VERSION 5.7 ;
  NOWIREEXTENSIONATPIN ON ;
  DIVIDERCHAR "/" ;
  BUSBITCHARS "[]" ;
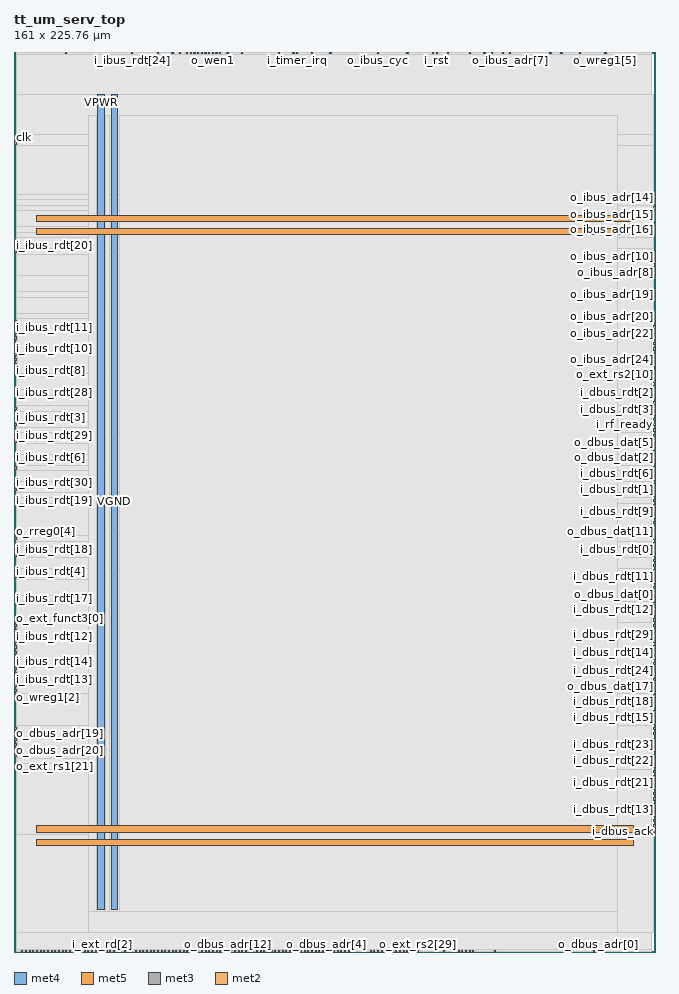
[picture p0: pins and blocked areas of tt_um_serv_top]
MACRO tt_um_serv_top
  CLASS BLOCK ;
  FOREIGN tt_um_serv_top ;
  ORIGIN 0.000 0.000 ;
  SIZE 161.000 BY 225.760 ;
  PIN VGND
    DIRECTION INOUT ;
    USE GROUND ;
    PORT
      LAYER met4 ;
        RECT 24.340 10.640 25.940 215.120 ;
    END
    PORT
      LAYER met5 ;
        RECT 5.520 30.030 155.480 31.630 ;
    END
    PORT
      LAYER met5 ;
        RECT 5.520 183.210 155.480 184.810 ;
    END
  END VGND
  PIN VPWR
    DIRECTION INOUT ;
    USE POWER ;
    PORT
      LAYER met4 ;
        RECT 21.040 10.640 22.640 215.120 ;
    END
    PORT
      LAYER met5 ;
        RECT 5.520 26.730 155.480 28.330 ;
    END
    PORT
      LAYER met5 ;
        RECT 5.520 179.910 155.480 181.510 ;
    END
  END VPWR
  PIN clk
    DIRECTION INPUT ;
    USE SIGNAL ;
    ANTENNAGATEAREA 0.852000 ;
    PORT
      LAYER met3 ;
        RECT 0.000 204.040 0.600 204.640 ;
    END
  END clk
  PIN i_dbus_ack
    DIRECTION INPUT ;
    USE SIGNAL ;
    ANTENNAGATEAREA 0.213000 ;
    PORT
      LAYER met3 ;
        RECT 160.400 29.960 161.000 30.560 ;
    END
  END i_dbus_ack
  PIN i_dbus_rdt[0]
    DIRECTION INPUT ;
    USE SIGNAL ;
    ANTENNAGATEAREA 0.213000 ;
    PORT
      LAYER met3 ;
        RECT 160.400 100.680 161.000 101.280 ;
    END
  END i_dbus_rdt[0]
  PIN i_dbus_rdt[10]
    DIRECTION INPUT ;
    USE SIGNAL ;
    ANTENNAGATEAREA 0.213000 ;
    PORT
      LAYER met3 ;
        RECT 160.400 141.480 161.000 142.080 ;
    END
  END i_dbus_rdt[10]
  PIN i_dbus_rdt[11]
    DIRECTION INPUT ;
    USE SIGNAL ;
    ANTENNAGATEAREA 0.213000 ;
    PORT
      LAYER met3 ;
        RECT 160.400 93.880 161.000 94.480 ;
    END
  END i_dbus_rdt[11]
  PIN i_dbus_rdt[12]
    DIRECTION INPUT ;
    USE SIGNAL ;
    ANTENNAGATEAREA 0.213000 ;
    PORT
      LAYER met3 ;
        RECT 160.400 85.720 161.000 86.320 ;
    END
  END i_dbus_rdt[12]
  PIN i_dbus_rdt[13]
    DIRECTION INPUT ;
    USE SIGNAL ;
    ANTENNAGATEAREA 0.213000 ;
    PORT
      LAYER met3 ;
        RECT 160.400 35.400 161.000 36.000 ;
    END
  END i_dbus_rdt[13]
  PIN i_dbus_rdt[14]
    DIRECTION INPUT ;
    USE SIGNAL ;
    ANTENNAGATEAREA 0.213000 ;
    PORT
      LAYER met3 ;
        RECT 160.400 74.840 161.000 75.440 ;
    END
  END i_dbus_rdt[14]
  PIN i_dbus_rdt[15]
    DIRECTION INPUT ;
    USE SIGNAL ;
    ANTENNAGATEAREA 0.213000 ;
    PORT
      LAYER met3 ;
        RECT 160.400 58.520 161.000 59.120 ;
    END
  END i_dbus_rdt[15]
  PIN i_dbus_rdt[16]
    DIRECTION INPUT ;
    USE SIGNAL ;
    ANTENNAGATEAREA 0.213000 ;
    PORT
      LAYER met3 ;
        RECT 160.400 76.200 161.000 76.800 ;
    END
  END i_dbus_rdt[16]
  PIN i_dbus_rdt[17]
    DIRECTION INPUT ;
    USE SIGNAL ;
    ANTENNAGATEAREA 0.213000 ;
    PORT
      LAYER met3 ;
        RECT 160.400 65.320 161.000 65.920 ;
    END
  END i_dbus_rdt[17]
  PIN i_dbus_rdt[18]
    DIRECTION INPUT ;
    USE SIGNAL ;
    ANTENNAGATEAREA 0.213000 ;
    PORT
      LAYER met3 ;
        RECT 160.400 62.600 161.000 63.200 ;
    END
  END i_dbus_rdt[18]
  PIN i_dbus_rdt[19]
    DIRECTION INPUT ;
    USE SIGNAL ;
    ANTENNAGATEAREA 0.213000 ;
    PORT
      LAYER met3 ;
        RECT 160.400 57.160 161.000 57.760 ;
    END
  END i_dbus_rdt[19]
  PIN i_dbus_rdt[1]
    DIRECTION INPUT ;
    USE SIGNAL ;
    ANTENNAGATEAREA 0.213000 ;
    PORT
      LAYER met3 ;
        RECT 160.400 115.640 161.000 116.240 ;
    END
  END i_dbus_rdt[1]
  PIN i_dbus_rdt[20]
    DIRECTION INPUT ;
    USE SIGNAL ;
    ANTENNAGATEAREA 0.213000 ;
    PORT
      LAYER met3 ;
        RECT 160.400 38.120 161.000 38.720 ;
    END
  END i_dbus_rdt[20]
  PIN i_dbus_rdt[21]
    DIRECTION INPUT ;
    USE SIGNAL ;
    ANTENNAGATEAREA 0.213000 ;
    PORT
      LAYER met3 ;
        RECT 160.400 42.200 161.000 42.800 ;
    END
  END i_dbus_rdt[21]
  PIN i_dbus_rdt[22]
    DIRECTION INPUT ;
    USE SIGNAL ;
    ANTENNAGATEAREA 0.213000 ;
    PORT
      LAYER met3 ;
        RECT 160.400 47.640 161.000 48.240 ;
    END
  END i_dbus_rdt[22]
  PIN i_dbus_rdt[23]
    DIRECTION INPUT ;
    USE SIGNAL ;
    ANTENNAGATEAREA 0.213000 ;
    PORT
      LAYER met3 ;
        RECT 160.400 51.720 161.000 52.320 ;
    END
  END i_dbus_rdt[23]
  PIN i_dbus_rdt[24]
    DIRECTION INPUT ;
    USE SIGNAL ;
    ANTENNAGATEAREA 0.213000 ;
    PORT
      LAYER met3 ;
        RECT 160.400 72.120 161.000 72.720 ;
    END
  END i_dbus_rdt[24]
  PIN i_dbus_rdt[25]
    DIRECTION INPUT ;
    USE SIGNAL ;
    ANTENNAGATEAREA 0.213000 ;
    PORT
      LAYER met2 ;
        RECT 114.170 0.000 114.450 0.280 ;
    END
  END i_dbus_rdt[25]
  PIN i_dbus_rdt[26]
    DIRECTION INPUT ;
    USE SIGNAL ;
    ANTENNAGATEAREA 0.213000 ;
    PORT
      LAYER met2 ;
        RECT 112.330 0.000 112.610 0.280 ;
    END
  END i_dbus_rdt[26]
  PIN i_dbus_rdt[27]
    DIRECTION INPUT ;
    USE SIGNAL ;
    ANTENNAGATEAREA 0.213000 ;
    PORT
      LAYER met2 ;
        RECT 107.730 0.000 108.010 0.280 ;
    END
  END i_dbus_rdt[27]
  PIN i_dbus_rdt[28]
    DIRECTION INPUT ;
    USE SIGNAL ;
    ANTENNAGATEAREA 0.213000 ;
    PORT
      LAYER met2 ;
        RECT 97.610 0.000 97.890 0.280 ;
    END
  END i_dbus_rdt[28]
  PIN i_dbus_rdt[29]
    DIRECTION INPUT ;
    USE SIGNAL ;
    ANTENNAGATEAREA 0.213000 ;
    PORT
      LAYER met3 ;
        RECT 160.400 77.560 161.000 78.160 ;
    END
  END i_dbus_rdt[29]
  PIN i_dbus_rdt[2]
    DIRECTION INPUT ;
    USE SIGNAL ;
    ANTENNAGATEAREA 0.213000 ;
    PORT
      LAYER met3 ;
        RECT 160.400 140.120 161.000 140.720 ;
    END
  END i_dbus_rdt[2]
  PIN i_dbus_rdt[30]
    DIRECTION INPUT ;
    USE SIGNAL ;
    ANTENNAGATEAREA 0.213000 ;
    PORT
      LAYER met2 ;
        RECT 92.090 0.000 92.370 0.280 ;
    END
  END i_dbus_rdt[30]
  PIN i_dbus_rdt[31]
    DIRECTION INPUT ;
    USE SIGNAL ;
    ANTENNAGATEAREA 0.213000 ;
    PORT
      LAYER met2 ;
        RECT 87.490 0.000 87.770 0.280 ;
    END
  END i_dbus_rdt[31]
  PIN i_dbus_rdt[3]
    DIRECTION INPUT ;
    USE SIGNAL ;
    ANTENNAGATEAREA 0.213000 ;
    PORT
      LAYER met3 ;
        RECT 160.400 137.400 161.000 138.000 ;
    END
  END i_dbus_rdt[3]
  PIN i_dbus_rdt[4]
    DIRECTION INPUT ;
    USE SIGNAL ;
    ANTENNAGATEAREA 0.213000 ;
    PORT
      LAYER met3 ;
        RECT 160.400 122.440 161.000 123.040 ;
    END
  END i_dbus_rdt[4]
  PIN i_dbus_rdt[5]
    DIRECTION INPUT ;
    USE SIGNAL ;
    ANTENNAGATEAREA 0.213000 ;
    PORT
      LAYER met3 ;
        RECT 160.400 121.080 161.000 121.680 ;
    END
  END i_dbus_rdt[5]
  PIN i_dbus_rdt[6]
    DIRECTION INPUT ;
    USE SIGNAL ;
    ANTENNAGATEAREA 0.213000 ;
    PORT
      LAYER met3 ;
        RECT 160.400 119.720 161.000 120.320 ;
    END
  END i_dbus_rdt[6]
  PIN i_dbus_rdt[7]
    DIRECTION INPUT ;
    USE SIGNAL ;
    ANTENNAGATEAREA 0.213000 ;
    PORT
      LAYER met3 ;
        RECT 160.400 102.040 161.000 102.640 ;
    END
  END i_dbus_rdt[7]
  PIN i_dbus_rdt[8]
    DIRECTION INPUT ;
    USE SIGNAL ;
    ANTENNAGATEAREA 0.213000 ;
    PORT
      LAYER met3 ;
        RECT 160.400 99.320 161.000 99.920 ;
    END
  END i_dbus_rdt[8]
  PIN i_dbus_rdt[9]
    DIRECTION INPUT ;
    USE SIGNAL ;
    ANTENNAGATEAREA 0.213000 ;
    PORT
      LAYER met3 ;
        RECT 160.400 110.200 161.000 110.800 ;
    END
  END i_dbus_rdt[9]
  PIN i_ext_rd[0]
    DIRECTION INPUT ;
    USE SIGNAL ;
    PORT
      LAYER met2 ;
        RECT 9.290 0.000 9.570 0.280 ;
    END
  END i_ext_rd[0]
  PIN i_ext_rd[10]
    DIRECTION INPUT ;
    USE SIGNAL ;
    PORT
      LAYER met2 ;
        RECT 4.690 0.000 4.970 0.280 ;
    END
  END i_ext_rd[10]
  PIN i_ext_rd[11]
    DIRECTION INPUT ;
    USE SIGNAL ;
    PORT
      LAYER met2 ;
        RECT 58.970 0.000 59.250 0.280 ;
    END
  END i_ext_rd[11]
  PIN i_ext_rd[12]
    DIRECTION INPUT ;
    USE SIGNAL ;
    PORT
      LAYER met2 ;
        RECT 14.810 0.000 15.090 0.280 ;
    END
  END i_ext_rd[12]
  PIN i_ext_rd[13]
    DIRECTION INPUT ;
    USE SIGNAL ;
    PORT
      LAYER met2 ;
        RECT 5.610 0.000 5.890 0.280 ;
    END
  END i_ext_rd[13]
  PIN i_ext_rd[14]
    DIRECTION INPUT ;
    USE SIGNAL ;
    PORT
      LAYER met2 ;
        RECT 12.970 0.000 13.250 0.280 ;
    END
  END i_ext_rd[14]
  PIN i_ext_rd[15]
    DIRECTION INPUT ;
    USE SIGNAL ;
    PORT
      LAYER met2 ;
        RECT 13.890 0.000 14.170 0.280 ;
    END
  END i_ext_rd[15]
  PIN i_ext_rd[16]
    DIRECTION INPUT ;
    USE SIGNAL ;
    PORT
      LAYER met2 ;
        RECT 2.850 0.000 3.130 0.280 ;
    END
  END i_ext_rd[16]
  PIN i_ext_rd[17]
    DIRECTION INPUT ;
    USE SIGNAL ;
    PORT
      LAYER met2 ;
        RECT 21.250 0.000 21.530 0.280 ;
    END
  END i_ext_rd[17]
  PIN i_ext_rd[18]
    DIRECTION INPUT ;
    USE SIGNAL ;
    PORT
      LAYER met2 ;
        RECT 16.650 0.000 16.930 0.280 ;
    END
  END i_ext_rd[18]
  PIN i_ext_rd[19]
    DIRECTION INPUT ;
    USE SIGNAL ;
    PORT
      LAYER met2 ;
        RECT 11.130 0.000 11.410 0.280 ;
    END
  END i_ext_rd[19]
  PIN i_ext_rd[1]
    DIRECTION INPUT ;
    USE SIGNAL ;
    PORT
      LAYER met2 ;
        RECT 15.730 0.000 16.010 0.280 ;
    END
  END i_ext_rd[1]
  PIN i_ext_rd[20]
    DIRECTION INPUT ;
    USE SIGNAL ;
    PORT
      LAYER met2 ;
        RECT 17.570 0.000 17.850 0.280 ;
    END
  END i_ext_rd[20]
  PIN i_ext_rd[21]
    DIRECTION INPUT ;
    USE SIGNAL ;
    PORT
      LAYER met2 ;
        RECT 69.090 0.000 69.370 0.280 ;
    END
  END i_ext_rd[21]
  PIN i_ext_rd[22]
    DIRECTION INPUT ;
    USE SIGNAL ;
    PORT
      LAYER met2 ;
        RECT 67.250 0.000 67.530 0.280 ;
    END
  END i_ext_rd[22]
  PIN i_ext_rd[23]
    DIRECTION INPUT ;
    USE SIGNAL ;
    PORT
      LAYER met2 ;
        RECT 20.330 0.000 20.610 0.280 ;
    END
  END i_ext_rd[23]
  PIN i_ext_rd[24]
    DIRECTION INPUT ;
    USE SIGNAL ;
    PORT
      LAYER met2 ;
        RECT 75.530 0.000 75.810 0.280 ;
    END
  END i_ext_rd[24]
  PIN i_ext_rd[25]
    DIRECTION INPUT ;
    USE SIGNAL ;
    PORT
      LAYER met2 ;
        RECT 83.810 0.000 84.090 0.280 ;
    END
  END i_ext_rd[25]
  PIN i_ext_rd[26]
    DIRECTION INPUT ;
    USE SIGNAL ;
    PORT
      LAYER met2 ;
        RECT 18.490 0.000 18.770 0.280 ;
    END
  END i_ext_rd[26]
  PIN i_ext_rd[27]
    DIRECTION INPUT ;
    USE SIGNAL ;
    PORT
      LAYER met2 ;
        RECT 19.410 0.000 19.690 0.280 ;
    END
  END i_ext_rd[27]
  PIN i_ext_rd[28]
    DIRECTION INPUT ;
    USE SIGNAL ;
    PORT
      LAYER met2 ;
        RECT 36.890 0.000 37.170 0.280 ;
    END
  END i_ext_rd[28]
  PIN i_ext_rd[29]
    DIRECTION INPUT ;
    USE SIGNAL ;
    PORT
      LAYER met2 ;
        RECT 1.930 0.000 2.210 0.280 ;
    END
  END i_ext_rd[29]
  PIN i_ext_rd[2]
    DIRECTION INPUT ;
    USE SIGNAL ;
    PORT
      LAYER met2 ;
        RECT 22.170 0.000 22.450 0.280 ;
    END
  END i_ext_rd[2]
  PIN i_ext_rd[30]
    DIRECTION INPUT ;
    USE SIGNAL ;
    PORT
      LAYER met2 ;
        RECT 3.770 0.000 4.050 0.280 ;
    END
  END i_ext_rd[30]
  PIN i_ext_rd[31]
    DIRECTION INPUT ;
    USE SIGNAL ;
    PORT
      LAYER met2 ;
        RECT 8.370 0.000 8.650 0.280 ;
    END
  END i_ext_rd[31]
  PIN i_ext_rd[3]
    DIRECTION INPUT ;
    USE SIGNAL ;
    PORT
      LAYER met2 ;
        RECT 6.530 0.000 6.810 0.280 ;
    END
  END i_ext_rd[3]
  PIN i_ext_rd[4]
    DIRECTION INPUT ;
    USE SIGNAL ;
    PORT
      LAYER met2 ;
        RECT 54.370 0.000 54.650 0.280 ;
    END
  END i_ext_rd[4]
  PIN i_ext_rd[5]
    DIRECTION INPUT ;
    USE SIGNAL ;
    PORT
      LAYER met2 ;
        RECT 7.450 0.000 7.730 0.280 ;
    END
  END i_ext_rd[5]
  PIN i_ext_rd[6]
    DIRECTION INPUT ;
    USE SIGNAL ;
    PORT
      LAYER met2 ;
        RECT 38.730 0.000 39.010 0.280 ;
    END
  END i_ext_rd[6]
  PIN i_ext_rd[7]
    DIRECTION INPUT ;
    USE SIGNAL ;
    PORT
      LAYER met2 ;
        RECT 10.210 0.000 10.490 0.280 ;
    END
  END i_ext_rd[7]
  PIN i_ext_rd[8]
    DIRECTION INPUT ;
    USE SIGNAL ;
    PORT
      LAYER met2 ;
        RECT 55.290 0.000 55.570 0.280 ;
    END
  END i_ext_rd[8]
  PIN i_ext_rd[9]
    DIRECTION INPUT ;
    USE SIGNAL ;
    PORT
      LAYER met2 ;
        RECT 30.450 0.000 30.730 0.280 ;
    END
  END i_ext_rd[9]
  PIN i_ext_ready
    DIRECTION INPUT ;
    USE SIGNAL ;
    PORT
      LAYER met2 ;
        RECT 31.370 0.000 31.650 0.280 ;
    END
  END i_ext_ready
  PIN i_ibus_ack
    DIRECTION INPUT ;
    USE SIGNAL ;
    ANTENNAGATEAREA 0.213000 ;
    PORT
      LAYER met3 ;
        RECT 0.000 202.680 0.600 203.280 ;
    END
  END i_ibus_ack
  PIN i_ibus_rdt[0]
    DIRECTION INPUT ;
    USE SIGNAL ;
    PORT
      LAYER met2 ;
        RECT 65.410 0.000 65.690 0.280 ;
    END
  END i_ibus_rdt[0]
  PIN i_ibus_rdt[10]
    DIRECTION INPUT ;
    USE SIGNAL ;
    ANTENNAGATEAREA 0.213000 ;
    PORT
      LAYER met3 ;
        RECT 0.000 151.000 0.600 151.600 ;
    END
  END i_ibus_rdt[10]
  PIN i_ibus_rdt[11]
    DIRECTION INPUT ;
    USE SIGNAL ;
    ANTENNAGATEAREA 0.213000 ;
    PORT
      LAYER met3 ;
        RECT 0.000 156.440 0.600 157.040 ;
    END
  END i_ibus_rdt[11]
  PIN i_ibus_rdt[12]
    DIRECTION INPUT ;
    USE SIGNAL ;
    ANTENNAGATEAREA 0.213000 ;
    PORT
      LAYER met3 ;
        RECT 0.000 78.920 0.600 79.520 ;
    END
  END i_ibus_rdt[12]
  PIN i_ibus_rdt[13]
    DIRECTION INPUT ;
    USE SIGNAL ;
    ANTENNAGATEAREA 0.213000 ;
    PORT
      LAYER met3 ;
        RECT 0.000 68.040 0.600 68.640 ;
    END
  END i_ibus_rdt[13]
  PIN i_ibus_rdt[14]
    DIRECTION INPUT ;
    USE SIGNAL ;
    ANTENNAGATEAREA 0.213000 ;
    PORT
      LAYER met3 ;
        RECT 0.000 70.760 0.600 71.360 ;
    END
  END i_ibus_rdt[14]
  PIN i_ibus_rdt[15]
    DIRECTION INPUT ;
    USE SIGNAL ;
    ANTENNAGATEAREA 0.213000 ;
    PORT
      LAYER met3 ;
        RECT 0.000 72.120 0.600 72.720 ;
    END
  END i_ibus_rdt[15]
  PIN i_ibus_rdt[16]
    DIRECTION INPUT ;
    USE SIGNAL ;
    ANTENNAGATEAREA 0.213000 ;
    PORT
      LAYER met3 ;
        RECT 0.000 77.560 0.600 78.160 ;
    END
  END i_ibus_rdt[16]
  PIN i_ibus_rdt[17]
    DIRECTION INPUT ;
    USE SIGNAL ;
    ANTENNAGATEAREA 0.213000 ;
    PORT
      LAYER met3 ;
        RECT 0.000 88.440 0.600 89.040 ;
    END
  END i_ibus_rdt[17]
  PIN i_ibus_rdt[18]
    DIRECTION INPUT ;
    USE SIGNAL ;
    ANTENNAGATEAREA 0.213000 ;
    PORT
      LAYER met3 ;
        RECT 0.000 100.680 0.600 101.280 ;
    END
  END i_ibus_rdt[18]
  PIN i_ibus_rdt[19]
    DIRECTION INPUT ;
    USE SIGNAL ;
    ANTENNAGATEAREA 0.213000 ;
    PORT
      LAYER met3 ;
        RECT 0.000 112.920 0.600 113.520 ;
    END
  END i_ibus_rdt[19]
  PIN i_ibus_rdt[1]
    DIRECTION INPUT ;
    USE SIGNAL ;
    PORT
      LAYER met2 ;
        RECT 70.010 0.000 70.290 0.280 ;
    END
  END i_ibus_rdt[1]
  PIN i_ibus_rdt[20]
    DIRECTION INPUT ;
    USE SIGNAL ;
    ANTENNAGATEAREA 0.213000 ;
    PORT
      LAYER met3 ;
        RECT 0.000 176.840 0.600 177.440 ;
    END
  END i_ibus_rdt[20]
  PIN i_ibus_rdt[21]
    DIRECTION INPUT ;
    USE SIGNAL ;
    ANTENNAGATEAREA 0.213000 ;
    PORT
      LAYER met2 ;
        RECT 50.690 225.480 50.970 225.760 ;
    END
  END i_ibus_rdt[21]
  PIN i_ibus_rdt[22]
    DIRECTION INPUT ;
    USE SIGNAL ;
    ANTENNAGATEAREA 0.213000 ;
    PORT
      LAYER met2 ;
        RECT 53.450 225.480 53.730 225.760 ;
    END
  END i_ibus_rdt[22]
  PIN i_ibus_rdt[23]
    DIRECTION INPUT ;
    USE SIGNAL ;
    ANTENNAGATEAREA 0.213000 ;
    PORT
      LAYER met2 ;
        RECT 35.970 225.480 36.250 225.760 ;
    END
  END i_ibus_rdt[23]
  PIN i_ibus_rdt[24]
    DIRECTION INPUT ;
    USE SIGNAL ;
    ANTENNAGATEAREA 0.213000 ;
    PORT
      LAYER met2 ;
        RECT 29.530 225.480 29.810 225.760 ;
    END
  END i_ibus_rdt[24]
  PIN i_ibus_rdt[25]
    DIRECTION INPUT ;
    USE SIGNAL ;
    ANTENNAGATEAREA 0.213000 ;
    PORT
      LAYER met3 ;
        RECT 0.000 178.200 0.600 178.800 ;
    END
  END i_ibus_rdt[25]
  PIN i_ibus_rdt[26]
    DIRECTION INPUT ;
    USE SIGNAL ;
    ANTENNAGATEAREA 0.213000 ;
    PORT
      LAYER met3 ;
        RECT 0.000 175.480 0.600 176.080 ;
    END
  END i_ibus_rdt[26]
  PIN i_ibus_rdt[27]
    DIRECTION INPUT ;
    USE SIGNAL ;
    ANTENNAGATEAREA 0.213000 ;
    PORT
      LAYER met3 ;
        RECT 0.000 157.800 0.600 158.400 ;
    END
  END i_ibus_rdt[27]
  PIN i_ibus_rdt[28]
    DIRECTION INPUT ;
    USE SIGNAL ;
    ANTENNAGATEAREA 0.213000 ;
    PORT
      LAYER met3 ;
        RECT 0.000 140.120 0.600 140.720 ;
    END
  END i_ibus_rdt[28]
  PIN i_ibus_rdt[29]
    DIRECTION INPUT ;
    USE SIGNAL ;
    ANTENNAGATEAREA 0.213000 ;
    PORT
      LAYER met3 ;
        RECT 0.000 129.240 0.600 129.840 ;
    END
  END i_ibus_rdt[29]
  PIN i_ibus_rdt[2]
    DIRECTION INPUT ;
    USE SIGNAL ;
    ANTENNAGATEAREA 0.213000 ;
    PORT
      LAYER met2 ;
        RECT 47.930 225.480 48.210 225.760 ;
    END
  END i_ibus_rdt[2]
  PIN i_ibus_rdt[30]
    DIRECTION INPUT ;
    USE SIGNAL ;
    ANTENNAGATEAREA 0.213000 ;
    PORT
      LAYER met3 ;
        RECT 0.000 115.640 0.600 116.240 ;
    END
  END i_ibus_rdt[30]
  PIN i_ibus_rdt[31]
    DIRECTION INPUT ;
    USE SIGNAL ;
    ANTENNAGATEAREA 0.213000 ;
    PORT
      LAYER met3 ;
        RECT 0.000 117.000 0.600 117.600 ;
    END
  END i_ibus_rdt[31]
  PIN i_ibus_rdt[3]
    DIRECTION INPUT ;
    USE SIGNAL ;
    ANTENNAGATEAREA 0.213000 ;
    PORT
      LAYER met3 ;
        RECT 0.000 131.960 0.600 132.560 ;
    END
  END i_ibus_rdt[3]
  PIN i_ibus_rdt[4]
    DIRECTION INPUT ;
    USE SIGNAL ;
    ANTENNAGATEAREA 0.213000 ;
    PORT
      LAYER met3 ;
        RECT 0.000 95.240 0.600 95.840 ;
    END
  END i_ibus_rdt[4]
  PIN i_ibus_rdt[5]
    DIRECTION INPUT ;
    USE SIGNAL ;
    ANTENNAGATEAREA 0.213000 ;
    PORT
      LAYER met2 ;
        RECT 57.130 225.480 57.410 225.760 ;
    END
  END i_ibus_rdt[5]
  PIN i_ibus_rdt[6]
    DIRECTION INPUT ;
    USE SIGNAL ;
    ANTENNAGATEAREA 0.213000 ;
    PORT
      LAYER met3 ;
        RECT 0.000 123.800 0.600 124.400 ;
    END
  END i_ibus_rdt[6]
  PIN i_ibus_rdt[7]
    DIRECTION INPUT ;
    USE SIGNAL ;
    ANTENNAGATEAREA 0.213000 ;
    PORT
      LAYER met3 ;
        RECT 0.000 127.880 0.600 128.480 ;
    END
  END i_ibus_rdt[7]
  PIN i_ibus_rdt[8]
    DIRECTION INPUT ;
    USE SIGNAL ;
    ANTENNAGATEAREA 0.213000 ;
    PORT
      LAYER met3 ;
        RECT 0.000 145.560 0.600 146.160 ;
    END
  END i_ibus_rdt[8]
  PIN i_ibus_rdt[9]
    DIRECTION INPUT ;
    USE SIGNAL ;
    ANTENNAGATEAREA 0.213000 ;
    PORT
      LAYER met3 ;
        RECT 0.000 146.920 0.600 147.520 ;
    END
  END i_ibus_rdt[9]
  PIN i_rdata0
    DIRECTION INPUT ;
    USE SIGNAL ;
    ANTENNAGATEAREA 0.213000 ;
    PORT
      LAYER met3 ;
        RECT 0.000 99.320 0.600 99.920 ;
    END
  END i_rdata0
  PIN i_rdata1
    DIRECTION INPUT ;
    USE SIGNAL ;
    ANTENNAGATEAREA 0.213000 ;
    PORT
      LAYER met2 ;
        RECT 79.210 225.480 79.490 225.760 ;
    END
  END i_rdata1
  PIN i_rf_ready
    DIRECTION INPUT ;
    USE SIGNAL ;
    ANTENNAGATEAREA 0.213000 ;
    PORT
      LAYER met3 ;
        RECT 160.400 131.960 161.000 132.560 ;
    END
  END i_rf_ready
  PIN i_rst
    DIRECTION INPUT ;
    USE SIGNAL ;
    ANTENNAGATEAREA 0.213000 ;
    PORT
      LAYER met2 ;
        RECT 105.890 225.480 106.170 225.760 ;
    END
  END i_rst
  PIN i_timer_irq
    DIRECTION INPUT ;
    USE SIGNAL ;
    ANTENNAGATEAREA 0.213000 ;
    PORT
      LAYER met2 ;
        RECT 70.930 225.480 71.210 225.760 ;
    END
  END i_timer_irq
  PIN o_dbus_adr[0]
    DIRECTION OUTPUT ;
    USE SIGNAL ;
    PORT
      LAYER met2 ;
        RECT 146.370 0.000 146.650 0.280 ;
    END
  END o_dbus_adr[0]
  PIN o_dbus_adr[10]
    DIRECTION OUTPUT ;
    USE SIGNAL ;
    ANTENNADIFFAREA 0.702900 ;
    PORT
      LAYER met2 ;
        RECT 62.650 0.000 62.930 0.280 ;
    END
  END o_dbus_adr[10]
  PIN o_dbus_adr[11]
    DIRECTION OUTPUT ;
    USE SIGNAL ;
    ANTENNADIFFAREA 0.702900 ;
    PORT
      LAYER met2 ;
        RECT 58.050 0.000 58.330 0.280 ;
    END
  END o_dbus_adr[11]
  PIN o_dbus_adr[12]
    DIRECTION OUTPUT ;
    USE SIGNAL ;
    ANTENNADIFFAREA 0.702900 ;
    PORT
      LAYER met2 ;
        RECT 53.450 0.000 53.730 0.280 ;
    END
  END o_dbus_adr[12]
  PIN o_dbus_adr[13]
    DIRECTION OUTPUT ;
    USE SIGNAL ;
    ANTENNADIFFAREA 0.702900 ;
    PORT
      LAYER met2 ;
        RECT 52.530 0.000 52.810 0.280 ;
    END
  END o_dbus_adr[13]
  PIN o_dbus_adr[14]
    DIRECTION OUTPUT ;
    USE SIGNAL ;
    ANTENNADIFFAREA 0.702900 ;
    PORT
      LAYER met2 ;
        RECT 46.090 0.000 46.370 0.280 ;
    END
  END o_dbus_adr[14]
  PIN o_dbus_adr[15]
    DIRECTION OUTPUT ;
    USE SIGNAL ;
    ANTENNADIFFAREA 0.702900 ;
    PORT
      LAYER met2 ;
        RECT 45.170 0.000 45.450 0.280 ;
    END
  END o_dbus_adr[15]
  PIN o_dbus_adr[16]
    DIRECTION OUTPUT ;
    USE SIGNAL ;
    ANTENNADIFFAREA 0.702900 ;
    PORT
      LAYER met2 ;
        RECT 42.410 0.000 42.690 0.280 ;
    END
  END o_dbus_adr[16]
  PIN o_dbus_adr[17]
    DIRECTION OUTPUT ;
    USE SIGNAL ;
    ANTENNADIFFAREA 0.702900 ;
    PORT
      LAYER met2 ;
        RECT 37.810 0.000 38.090 0.280 ;
    END
  END o_dbus_adr[17]
  PIN o_dbus_adr[18]
    DIRECTION OUTPUT ;
    USE SIGNAL ;
    ANTENNADIFFAREA 0.702900 ;
    PORT
      LAYER met2 ;
        RECT 33.210 0.000 33.490 0.280 ;
    END
  END o_dbus_adr[18]
  PIN o_dbus_adr[19]
    DIRECTION OUTPUT ;
    USE SIGNAL ;
    ANTENNADIFFAREA 0.702900 ;
    PORT
      LAYER met3 ;
        RECT 0.000 54.440 0.600 55.040 ;
    END
  END o_dbus_adr[19]
  PIN o_dbus_adr[1]
    DIRECTION OUTPUT ;
    USE SIGNAL ;
    PORT
      LAYER met2 ;
        RECT 12.970 225.480 13.250 225.760 ;
    END
  END o_dbus_adr[1]
  PIN o_dbus_adr[20]
    DIRECTION OUTPUT ;
    USE SIGNAL ;
    ANTENNADIFFAREA 0.702900 ;
    PORT
      LAYER met3 ;
        RECT 0.000 50.360 0.600 50.960 ;
    END
  END o_dbus_adr[20]
  PIN o_dbus_adr[21]
    DIRECTION OUTPUT ;
    USE SIGNAL ;
    ANTENNADIFFAREA 0.702900 ;
    PORT
      LAYER met3 ;
        RECT 0.000 49.000 0.600 49.600 ;
    END
  END o_dbus_adr[21]
  PIN o_dbus_adr[22]
    DIRECTION OUTPUT ;
    USE SIGNAL ;
    ANTENNADIFFAREA 0.702900 ;
    PORT
      LAYER met2 ;
        RECT 23.090 0.000 23.370 0.280 ;
    END
  END o_dbus_adr[22]
  PIN o_dbus_adr[23]
    DIRECTION OUTPUT ;
    USE SIGNAL ;
    ANTENNADIFFAREA 0.702900 ;
    PORT
      LAYER met2 ;
        RECT 24.010 0.000 24.290 0.280 ;
    END
  END o_dbus_adr[23]
  PIN o_dbus_adr[24]
    DIRECTION OUTPUT ;
    USE SIGNAL ;
    ANTENNADIFFAREA 0.702900 ;
    PORT
      LAYER met2 ;
        RECT 27.690 0.000 27.970 0.280 ;
    END
  END o_dbus_adr[24]
  PIN o_dbus_adr[25]
    DIRECTION OUTPUT ;
    USE SIGNAL ;
    ANTENNADIFFAREA 0.702900 ;
    PORT
      LAYER met2 ;
        RECT 28.610 0.000 28.890 0.280 ;
    END
  END o_dbus_adr[25]
  PIN o_dbus_adr[26]
    DIRECTION OUTPUT ;
    USE SIGNAL ;
    ANTENNADIFFAREA 0.702900 ;
    PORT
      LAYER met2 ;
        RECT 32.290 0.000 32.570 0.280 ;
    END
  END o_dbus_adr[26]
  PIN o_dbus_adr[27]
    DIRECTION OUTPUT ;
    USE SIGNAL ;
    ANTENNADIFFAREA 0.702900 ;
    PORT
      LAYER met2 ;
        RECT 35.050 0.000 35.330 0.280 ;
    END
  END o_dbus_adr[27]
  PIN o_dbus_adr[28]
    DIRECTION OUTPUT ;
    USE SIGNAL ;
    ANTENNADIFFAREA 0.702900 ;
    PORT
      LAYER met2 ;
        RECT 40.570 0.000 40.850 0.280 ;
    END
  END o_dbus_adr[28]
  PIN o_dbus_adr[29]
    DIRECTION OUTPUT ;
    USE SIGNAL ;
    ANTENNADIFFAREA 0.702900 ;
    PORT
      LAYER met2 ;
        RECT 49.770 0.000 50.050 0.280 ;
    END
  END o_dbus_adr[29]
  PIN o_dbus_adr[2]
    DIRECTION OUTPUT ;
    USE SIGNAL ;
    ANTENNADIFFAREA 0.702900 ;
    PORT
      LAYER met2 ;
        RECT 71.850 0.000 72.130 0.280 ;
    END
  END o_dbus_adr[2]
  PIN o_dbus_adr[30]
    DIRECTION OUTPUT ;
    USE SIGNAL ;
    ANTENNADIFFAREA 0.702900 ;
    PORT
      LAYER met2 ;
        RECT 50.690 0.000 50.970 0.280 ;
    END
  END o_dbus_adr[30]
  PIN o_dbus_adr[31]
    DIRECTION OUTPUT ;
    USE SIGNAL ;
    ANTENNADIFFAREA 0.702900 ;
    PORT
      LAYER met2 ;
        RECT 61.730 0.000 62.010 0.280 ;
    END
  END o_dbus_adr[31]
  PIN o_dbus_adr[3]
    DIRECTION OUTPUT ;
    USE SIGNAL ;
    ANTENNADIFFAREA 0.702900 ;
    PORT
      LAYER met2 ;
        RECT 74.610 0.000 74.890 0.280 ;
    END
  END o_dbus_adr[3]
  PIN o_dbus_adr[4]
    DIRECTION OUTPUT ;
    USE SIGNAL ;
    ANTENNADIFFAREA 0.702900 ;
    PORT
      LAYER met2 ;
        RECT 78.290 0.000 78.570 0.280 ;
    END
  END o_dbus_adr[4]
  PIN o_dbus_adr[5]
    DIRECTION OUTPUT ;
    USE SIGNAL ;
    ANTENNADIFFAREA 0.702900 ;
    PORT
      LAYER met2 ;
        RECT 82.890 0.000 83.170 0.280 ;
    END
  END o_dbus_adr[5]
  PIN o_dbus_adr[6]
    DIRECTION OUTPUT ;
    USE SIGNAL ;
    ANTENNADIFFAREA 0.702900 ;
    PORT
      LAYER met2 ;
        RECT 79.210 0.000 79.490 0.280 ;
    END
  END o_dbus_adr[6]
  PIN o_dbus_adr[7]
    DIRECTION OUTPUT ;
    USE SIGNAL ;
    ANTENNADIFFAREA 0.702900 ;
    PORT
      LAYER met2 ;
        RECT 72.770 0.000 73.050 0.280 ;
    END
  END o_dbus_adr[7]
  PIN o_dbus_adr[8]
    DIRECTION OUTPUT ;
    USE SIGNAL ;
    ANTENNADIFFAREA 0.702900 ;
    PORT
      LAYER met2 ;
        RECT 68.170 0.000 68.450 0.280 ;
    END
  END o_dbus_adr[8]
  PIN o_dbus_adr[9]
    DIRECTION OUTPUT ;
    USE SIGNAL ;
    ANTENNADIFFAREA 0.702900 ;
    PORT
      LAYER met2 ;
        RECT 64.490 0.000 64.770 0.280 ;
    END
  END o_dbus_adr[9]
  PIN o_dbus_cyc
    DIRECTION OUTPUT ;
    USE SIGNAL ;
    ANTENNADIFFAREA 0.702900 ;
    PORT
      LAYER met3 ;
        RECT 160.400 117.000 161.000 117.600 ;
    END
  END o_dbus_cyc
  PIN o_dbus_dat[0]
    DIRECTION OUTPUT ;
    USE SIGNAL ;
    ANTENNADIFFAREA 0.702900 ;
    PORT
      LAYER met3 ;
        RECT 160.400 91.160 161.000 91.760 ;
    END
  END o_dbus_dat[0]
  PIN o_dbus_dat[10]
    DIRECTION OUTPUT ;
    USE SIGNAL ;
    ANTENNADIFFAREA 0.702900 ;
    PORT
      LAYER met3 ;
        RECT 160.400 114.280 161.000 114.880 ;
    END
  END o_dbus_dat[10]
  PIN o_dbus_dat[11]
    DIRECTION OUTPUT ;
    USE SIGNAL ;
    ANTENNADIFFAREA 0.702900 ;
    PORT
      LAYER met3 ;
        RECT 160.400 103.400 161.000 104.000 ;
    END
  END o_dbus_dat[11]
  PIN o_dbus_dat[12]
    DIRECTION OUTPUT ;
    USE SIGNAL ;
    ANTENNADIFFAREA 0.702900 ;
    PORT
      LAYER met3 ;
        RECT 160.400 87.080 161.000 87.680 ;
    END
  END o_dbus_dat[12]
  PIN o_dbus_dat[13]
    DIRECTION OUTPUT ;
    USE SIGNAL ;
    ANTENNADIFFAREA 0.702900 ;
    PORT
      LAYER met3 ;
        RECT 160.400 80.280 161.000 80.880 ;
    END
  END o_dbus_dat[13]
  PIN o_dbus_dat[14]
    DIRECTION OUTPUT ;
    USE SIGNAL ;
    ANTENNADIFFAREA 0.702900 ;
    PORT
      LAYER met3 ;
        RECT 160.400 73.480 161.000 74.080 ;
    END
  END o_dbus_dat[14]
  PIN o_dbus_dat[15]
    DIRECTION OUTPUT ;
    USE SIGNAL ;
    ANTENNADIFFAREA 0.702900 ;
    PORT
      LAYER met3 ;
        RECT 160.400 59.880 161.000 60.480 ;
    END
  END o_dbus_dat[15]
  PIN o_dbus_dat[16]
    DIRECTION OUTPUT ;
    USE SIGNAL ;
    ANTENNADIFFAREA 0.702900 ;
    PORT
      LAYER met3 ;
        RECT 160.400 89.800 161.000 90.400 ;
    END
  END o_dbus_dat[16]
  PIN o_dbus_dat[17]
    DIRECTION OUTPUT ;
    USE SIGNAL ;
    ANTENNADIFFAREA 0.702900 ;
    PORT
      LAYER met3 ;
        RECT 160.400 68.040 161.000 68.640 ;
    END
  END o_dbus_dat[17]
  PIN o_dbus_dat[18]
    DIRECTION OUTPUT ;
    USE SIGNAL ;
    ANTENNADIFFAREA 0.702900 ;
    PORT
      LAYER met3 ;
        RECT 160.400 63.960 161.000 64.560 ;
    END
  END o_dbus_dat[18]
  PIN o_dbus_dat[19]
    DIRECTION OUTPUT ;
    USE SIGNAL ;
    ANTENNADIFFAREA 0.702900 ;
    PORT
      LAYER met3 ;
        RECT 160.400 55.800 161.000 56.400 ;
    END
  END o_dbus_dat[19]
  PIN o_dbus_dat[1]
    DIRECTION OUTPUT ;
    USE SIGNAL ;
    ANTENNADIFFAREA 0.702900 ;
    PORT
      LAYER met3 ;
        RECT 160.400 111.560 161.000 112.160 ;
    END
  END o_dbus_dat[1]
  PIN o_dbus_dat[20]
    DIRECTION OUTPUT ;
    USE SIGNAL ;
    ANTENNADIFFAREA 0.702900 ;
    PORT
      LAYER met3 ;
        RECT 160.400 53.080 161.000 53.680 ;
    END
  END o_dbus_dat[20]
  PIN o_dbus_dat[21]
    DIRECTION OUTPUT ;
    USE SIGNAL ;
    ANTENNADIFFAREA 0.702900 ;
    PORT
      LAYER met3 ;
        RECT 160.400 40.840 161.000 41.440 ;
    END
  END o_dbus_dat[21]
  PIN o_dbus_dat[22]
    DIRECTION OUTPUT ;
    USE SIGNAL ;
    ANTENNADIFFAREA 0.702900 ;
    PORT
      LAYER met3 ;
        RECT 160.400 49.000 161.000 49.600 ;
    END
  END o_dbus_dat[22]
  PIN o_dbus_dat[23]
    DIRECTION OUTPUT ;
    USE SIGNAL ;
    ANTENNADIFFAREA 0.702900 ;
    PORT
      LAYER met3 ;
        RECT 160.400 44.920 161.000 45.520 ;
    END
  END o_dbus_dat[23]
  PIN o_dbus_dat[24]
    DIRECTION OUTPUT ;
    USE SIGNAL ;
    ANTENNADIFFAREA 0.702900 ;
    PORT
      LAYER met3 ;
        RECT 160.400 39.480 161.000 40.080 ;
    END
  END o_dbus_dat[24]
  PIN o_dbus_dat[25]
    DIRECTION OUTPUT ;
    USE SIGNAL ;
    ANTENNADIFFAREA 0.702900 ;
    PORT
      LAYER met2 ;
        RECT 111.410 0.000 111.690 0.280 ;
    END
  END o_dbus_dat[25]
  PIN o_dbus_dat[26]
    DIRECTION OUTPUT ;
    USE SIGNAL ;
    ANTENNADIFFAREA 0.702900 ;
    PORT
      LAYER met2 ;
        RECT 115.090 0.000 115.370 0.280 ;
    END
  END o_dbus_dat[26]
  PIN o_dbus_dat[27]
    DIRECTION OUTPUT ;
    USE SIGNAL ;
    ANTENNADIFFAREA 0.702900 ;
    PORT
      LAYER met2 ;
        RECT 110.490 0.000 110.770 0.280 ;
    END
  END o_dbus_dat[27]
  PIN o_dbus_dat[28]
    DIRECTION OUTPUT ;
    USE SIGNAL ;
    ANTENNADIFFAREA 0.702900 ;
    PORT
      LAYER met2 ;
        RECT 96.690 0.000 96.970 0.280 ;
    END
  END o_dbus_dat[28]
  PIN o_dbus_dat[29]
    DIRECTION OUTPUT ;
    USE SIGNAL ;
    ANTENNADIFFAREA 0.702900 ;
    PORT
      LAYER met2 ;
        RECT 98.530 0.000 98.810 0.280 ;
    END
  END o_dbus_dat[29]
  PIN o_dbus_dat[2]
    DIRECTION OUTPUT ;
    USE SIGNAL ;
    ANTENNADIFFAREA 0.702900 ;
    PORT
      LAYER met3 ;
        RECT 160.400 123.800 161.000 124.400 ;
    END
  END o_dbus_dat[2]
  PIN o_dbus_dat[30]
    DIRECTION OUTPUT ;
    USE SIGNAL ;
    ANTENNADIFFAREA 0.702900 ;
    PORT
      LAYER met2 ;
        RECT 90.250 0.000 90.530 0.280 ;
    END
  END o_dbus_dat[30]
  PIN o_dbus_dat[31]
    DIRECTION OUTPUT ;
    USE SIGNAL ;
    ANTENNADIFFAREA 0.702900 ;
    PORT
      LAYER met2 ;
        RECT 89.330 0.000 89.610 0.280 ;
    END
  END o_dbus_dat[31]
  PIN o_dbus_dat[3]
    DIRECTION OUTPUT ;
    USE SIGNAL ;
    ANTENNADIFFAREA 0.702900 ;
    PORT
      LAYER met3 ;
        RECT 160.400 138.760 161.000 139.360 ;
    END
  END o_dbus_dat[3]
  PIN o_dbus_dat[4]
    DIRECTION OUTPUT ;
    USE SIGNAL ;
    ANTENNADIFFAREA 0.702900 ;
    PORT
      LAYER met3 ;
        RECT 160.400 126.520 161.000 127.120 ;
    END
  END o_dbus_dat[4]
  PIN o_dbus_dat[5]
    DIRECTION OUTPUT ;
    USE SIGNAL ;
    ANTENNADIFFAREA 0.702900 ;
    PORT
      LAYER met3 ;
        RECT 160.400 129.240 161.000 129.840 ;
    END
  END o_dbus_dat[5]
  PIN o_dbus_dat[6]
    DIRECTION OUTPUT ;
    USE SIGNAL ;
    ANTENNADIFFAREA 0.702900 ;
    PORT
      LAYER met3 ;
        RECT 160.400 136.040 161.000 136.640 ;
    END
  END o_dbus_dat[6]
  PIN o_dbus_dat[7]
    DIRECTION OUTPUT ;
    USE SIGNAL ;
    ANTENNADIFFAREA 0.702900 ;
    PORT
      LAYER met3 ;
        RECT 160.400 118.360 161.000 118.960 ;
    END
  END o_dbus_dat[7]
  PIN o_dbus_dat[8]
    DIRECTION OUTPUT ;
    USE SIGNAL ;
    ANTENNADIFFAREA 0.702900 ;
    PORT
      LAYER met3 ;
        RECT 160.400 92.520 161.000 93.120 ;
    END
  END o_dbus_dat[8]
  PIN o_dbus_dat[9]
    DIRECTION OUTPUT ;
    USE SIGNAL ;
    ANTENNADIFFAREA 0.702900 ;
    PORT
      LAYER met3 ;
        RECT 160.400 106.120 161.000 106.720 ;
    END
  END o_dbus_dat[9]
  PIN o_dbus_sel[0]
    DIRECTION OUTPUT ;
    USE SIGNAL ;
    ANTENNADIFFAREA 0.702900 ;
    PORT
      LAYER met3 ;
        RECT 160.400 31.320 161.000 31.920 ;
    END
  END o_dbus_sel[0]
  PIN o_dbus_sel[1]
    DIRECTION OUTPUT ;
    USE SIGNAL ;
    ANTENNADIFFAREA 0.702900 ;
    PORT
      LAYER met2 ;
        RECT 93.010 0.000 93.290 0.280 ;
    END
  END o_dbus_sel[1]
  PIN o_dbus_sel[2]
    DIRECTION OUTPUT ;
    USE SIGNAL ;
    ANTENNADIFFAREA 0.702900 ;
    PORT
      LAYER met2 ;
        RECT 95.770 0.000 96.050 0.280 ;
    END
  END o_dbus_sel[2]
  PIN o_dbus_sel[3]
    DIRECTION OUTPUT ;
    USE SIGNAL ;
    ANTENNADIFFAREA 0.702900 ;
    PORT
      LAYER met2 ;
        RECT 93.930 0.000 94.210 0.280 ;
    END
  END o_dbus_sel[3]
  PIN o_dbus_we
    DIRECTION OUTPUT ;
    USE SIGNAL ;
    ANTENNADIFFAREA 0.702900 ;
    PORT
      LAYER met2 ;
        RECT 70.010 225.480 70.290 225.760 ;
    END
  END o_dbus_we
  PIN o_ext_funct3[0]
    DIRECTION OUTPUT ;
    USE SIGNAL ;
    ANTENNADIFFAREA 0.702900 ;
    PORT
      LAYER met3 ;
        RECT 0.000 81.640 0.600 82.240 ;
    END
  END o_ext_funct3[0]
  PIN o_ext_funct3[1]
    DIRECTION OUTPUT ;
    USE SIGNAL ;
    ANTENNADIFFAREA 0.702900 ;
    PORT
      LAYER met3 ;
        RECT 0.000 69.400 0.600 70.000 ;
    END
  END o_ext_funct3[1]
  PIN o_ext_funct3[2]
    DIRECTION OUTPUT ;
    USE SIGNAL ;
    ANTENNADIFFAREA 0.702900 ;
    PORT
      LAYER met3 ;
        RECT 0.000 74.840 0.600 75.440 ;
    END
  END o_ext_funct3[2]
  PIN o_ext_rs1[0]
    DIRECTION OUTPUT ;
    USE SIGNAL ;
    ANTENNADIFFAREA 0.702900 ;
    PORT
      LAYER met3 ;
        RECT 160.400 54.440 161.000 55.040 ;
    END
  END o_ext_rs1[0]
  PIN o_ext_rs1[10]
    DIRECTION OUTPUT ;
    USE SIGNAL ;
    ANTENNADIFFAREA 0.702900 ;
    PORT
      LAYER met2 ;
        RECT 63.570 0.000 63.850 0.280 ;
    END
  END o_ext_rs1[10]
  PIN o_ext_rs1[11]
    DIRECTION OUTPUT ;
    USE SIGNAL ;
    ANTENNADIFFAREA 0.702900 ;
    PORT
      LAYER met2 ;
        RECT 59.890 0.000 60.170 0.280 ;
    END
  END o_ext_rs1[11]
  PIN o_ext_rs1[12]
    DIRECTION OUTPUT ;
    USE SIGNAL ;
    ANTENNADIFFAREA 0.702900 ;
    PORT
      LAYER met2 ;
        RECT 57.130 0.000 57.410 0.280 ;
    END
  END o_ext_rs1[12]
  PIN o_ext_rs1[13]
    DIRECTION OUTPUT ;
    USE SIGNAL ;
    ANTENNADIFFAREA 0.702900 ;
    PORT
      LAYER met2 ;
        RECT 51.610 0.000 51.890 0.280 ;
    END
  END o_ext_rs1[13]
  PIN o_ext_rs1[14]
    DIRECTION OUTPUT ;
    USE SIGNAL ;
    ANTENNADIFFAREA 0.702900 ;
    PORT
      LAYER met2 ;
        RECT 48.850 0.000 49.130 0.280 ;
    END
  END o_ext_rs1[14]
  PIN o_ext_rs1[15]
    DIRECTION OUTPUT ;
    USE SIGNAL ;
    ANTENNADIFFAREA 0.702900 ;
    PORT
      LAYER met2 ;
        RECT 47.010 0.000 47.290 0.280 ;
    END
  END o_ext_rs1[15]
  PIN o_ext_rs1[16]
    DIRECTION OUTPUT ;
    USE SIGNAL ;
    ANTENNADIFFAREA 0.702900 ;
    PORT
      LAYER met2 ;
        RECT 44.250 0.000 44.530 0.280 ;
    END
  END o_ext_rs1[16]
  PIN o_ext_rs1[17]
    DIRECTION OUTPUT ;
    USE SIGNAL ;
    ANTENNADIFFAREA 0.702900 ;
    PORT
      LAYER met2 ;
        RECT 41.490 0.000 41.770 0.280 ;
    END
  END o_ext_rs1[17]
  PIN o_ext_rs1[18]
    DIRECTION OUTPUT ;
    USE SIGNAL ;
    ANTENNADIFFAREA 0.702900 ;
    PORT
      LAYER met2 ;
        RECT 35.970 0.000 36.250 0.280 ;
    END
  END o_ext_rs1[18]
  PIN o_ext_rs1[19]
    DIRECTION OUTPUT ;
    USE SIGNAL ;
    ANTENNADIFFAREA 0.702900 ;
    PORT
      LAYER met3 ;
        RECT 0.000 53.080 0.600 53.680 ;
    END
  END o_ext_rs1[19]
  PIN o_ext_rs1[1]
    DIRECTION OUTPUT ;
    USE SIGNAL ;
    ANTENNADIFFAREA 0.702900 ;
    PORT
      LAYER met3 ;
        RECT 160.400 32.680 161.000 33.280 ;
    END
  END o_ext_rs1[1]
  PIN o_ext_rs1[20]
    DIRECTION OUTPUT ;
    USE SIGNAL ;
    ANTENNADIFFAREA 0.702900 ;
    PORT
      LAYER met3 ;
        RECT 0.000 51.720 0.600 52.320 ;
    END
  END o_ext_rs1[20]
  PIN o_ext_rs1[21]
    DIRECTION OUTPUT ;
    USE SIGNAL ;
    ANTENNADIFFAREA 0.702900 ;
    PORT
      LAYER met3 ;
        RECT 0.000 46.280 0.600 46.880 ;
    END
  END o_ext_rs1[21]
  PIN o_ext_rs1[22]
    DIRECTION OUTPUT ;
    USE SIGNAL ;
    ANTENNADIFFAREA 0.702900 ;
    PORT
      LAYER met2 ;
        RECT 24.930 0.000 25.210 0.280 ;
    END
  END o_ext_rs1[22]
  PIN o_ext_rs1[23]
    DIRECTION OUTPUT ;
    USE SIGNAL ;
    ANTENNADIFFAREA 0.702900 ;
    PORT
      LAYER met2 ;
        RECT 25.850 0.000 26.130 0.280 ;
    END
  END o_ext_rs1[23]
  PIN o_ext_rs1[24]
    DIRECTION OUTPUT ;
    USE SIGNAL ;
    ANTENNADIFFAREA 0.702900 ;
    PORT
      LAYER met2 ;
        RECT 26.770 0.000 27.050 0.280 ;
    END
  END o_ext_rs1[24]
  PIN o_ext_rs1[25]
    DIRECTION OUTPUT ;
    USE SIGNAL ;
    ANTENNADIFFAREA 0.702900 ;
    PORT
      LAYER met2 ;
        RECT 29.530 0.000 29.810 0.280 ;
    END
  END o_ext_rs1[25]
  PIN o_ext_rs1[26]
    DIRECTION OUTPUT ;
    USE SIGNAL ;
    ANTENNADIFFAREA 0.702900 ;
    PORT
      LAYER met2 ;
        RECT 34.130 0.000 34.410 0.280 ;
    END
  END o_ext_rs1[26]
  PIN o_ext_rs1[27]
    DIRECTION OUTPUT ;
    USE SIGNAL ;
    ANTENNADIFFAREA 0.702900 ;
    PORT
      LAYER met2 ;
        RECT 39.650 0.000 39.930 0.280 ;
    END
  END o_ext_rs1[27]
  PIN o_ext_rs1[28]
    DIRECTION OUTPUT ;
    USE SIGNAL ;
    ANTENNADIFFAREA 0.702900 ;
    PORT
      LAYER met2 ;
        RECT 43.330 0.000 43.610 0.280 ;
    END
  END o_ext_rs1[28]
  PIN o_ext_rs1[29]
    DIRECTION OUTPUT ;
    USE SIGNAL ;
    ANTENNADIFFAREA 0.702900 ;
    PORT
      LAYER met2 ;
        RECT 47.930 0.000 48.210 0.280 ;
    END
  END o_ext_rs1[29]
  PIN o_ext_rs1[2]
    DIRECTION OUTPUT ;
    USE SIGNAL ;
    ANTENNADIFFAREA 0.702900 ;
    PORT
      LAYER met2 ;
        RECT 73.690 0.000 73.970 0.280 ;
    END
  END o_ext_rs1[2]
  PIN o_ext_rs1[30]
    DIRECTION OUTPUT ;
    USE SIGNAL ;
    ANTENNADIFFAREA 0.702900 ;
    PORT
      LAYER met2 ;
        RECT 56.210 0.000 56.490 0.280 ;
    END
  END o_ext_rs1[30]
  PIN o_ext_rs1[31]
    DIRECTION OUTPUT ;
    USE SIGNAL ;
    ANTENNADIFFAREA 0.702900 ;
    PORT
      LAYER met2 ;
        RECT 60.810 0.000 61.090 0.280 ;
    END
  END o_ext_rs1[31]
  PIN o_ext_rs1[3]
    DIRECTION OUTPUT ;
    USE SIGNAL ;
    ANTENNADIFFAREA 0.702900 ;
    PORT
      LAYER met2 ;
        RECT 77.370 0.000 77.650 0.280 ;
    END
  END o_ext_rs1[3]
  PIN o_ext_rs1[4]
    DIRECTION OUTPUT ;
    USE SIGNAL ;
    ANTENNADIFFAREA 0.702900 ;
    PORT
      LAYER met2 ;
        RECT 81.050 0.000 81.330 0.280 ;
    END
  END o_ext_rs1[4]
  PIN o_ext_rs1[5]
    DIRECTION OUTPUT ;
    USE SIGNAL ;
    ANTENNADIFFAREA 0.702900 ;
    PORT
      LAYER met2 ;
        RECT 81.970 0.000 82.250 0.280 ;
    END
  END o_ext_rs1[5]
  PIN o_ext_rs1[6]
    DIRECTION OUTPUT ;
    USE SIGNAL ;
    ANTENNADIFFAREA 0.702900 ;
    PORT
      LAYER met2 ;
        RECT 80.130 0.000 80.410 0.280 ;
    END
  END o_ext_rs1[6]
  PIN o_ext_rs1[7]
    DIRECTION OUTPUT ;
    USE SIGNAL ;
    ANTENNADIFFAREA 0.702900 ;
    PORT
      LAYER met2 ;
        RECT 76.450 0.000 76.730 0.280 ;
    END
  END o_ext_rs1[7]
  PIN o_ext_rs1[8]
    DIRECTION OUTPUT ;
    USE SIGNAL ;
    ANTENNADIFFAREA 0.702900 ;
    PORT
      LAYER met2 ;
        RECT 70.930 0.000 71.210 0.280 ;
    END
  END o_ext_rs1[8]
  PIN o_ext_rs1[9]
    DIRECTION OUTPUT ;
    USE SIGNAL ;
    ANTENNADIFFAREA 0.702900 ;
    PORT
      LAYER met2 ;
        RECT 66.330 0.000 66.610 0.280 ;
    END
  END o_ext_rs1[9]
  PIN o_ext_rs2[0]
    DIRECTION OUTPUT ;
    USE SIGNAL ;
    ANTENNADIFFAREA 0.702900 ;
    PORT
      LAYER met3 ;
        RECT 160.400 95.240 161.000 95.840 ;
    END
  END o_ext_rs2[0]
  PIN o_ext_rs2[10]
    DIRECTION OUTPUT ;
    USE SIGNAL ;
    ANTENNADIFFAREA 0.702900 ;
    PORT
      LAYER met3 ;
        RECT 160.400 142.840 161.000 143.440 ;
    END
  END o_ext_rs2[10]
  PIN o_ext_rs2[11]
    DIRECTION OUTPUT ;
    USE SIGNAL ;
    ANTENNADIFFAREA 0.702900 ;
    PORT
      LAYER met3 ;
        RECT 160.400 97.960 161.000 98.560 ;
    END
  END o_ext_rs2[11]
  PIN o_ext_rs2[12]
    DIRECTION OUTPUT ;
    USE SIGNAL ;
    ANTENNADIFFAREA 0.702900 ;
    PORT
      LAYER met3 ;
        RECT 160.400 88.440 161.000 89.040 ;
    END
  END o_ext_rs2[12]
  PIN o_ext_rs2[13]
    DIRECTION OUTPUT ;
    USE SIGNAL ;
    ANTENNADIFFAREA 0.702900 ;
    PORT
      LAYER met3 ;
        RECT 160.400 81.640 161.000 82.240 ;
    END
  END o_ext_rs2[13]
  PIN o_ext_rs2[14]
    DIRECTION OUTPUT ;
    USE SIGNAL ;
    ANTENNADIFFAREA 0.702900 ;
    PORT
      LAYER met3 ;
        RECT 160.400 34.040 161.000 34.640 ;
    END
  END o_ext_rs2[14]
  PIN o_ext_rs2[15]
    DIRECTION OUTPUT ;
    USE SIGNAL ;
    ANTENNADIFFAREA 0.702900 ;
    PORT
      LAYER met3 ;
        RECT 160.400 78.920 161.000 79.520 ;
    END
  END o_ext_rs2[15]
  PIN o_ext_rs2[16]
    DIRECTION OUTPUT ;
    USE SIGNAL ;
    ANTENNADIFFAREA 0.702900 ;
    PORT
      LAYER met3 ;
        RECT 160.400 83.000 161.000 83.600 ;
    END
  END o_ext_rs2[16]
  PIN o_ext_rs2[17]
    DIRECTION OUTPUT ;
    USE SIGNAL ;
    ANTENNADIFFAREA 0.702900 ;
    PORT
      LAYER met3 ;
        RECT 160.400 70.760 161.000 71.360 ;
    END
  END o_ext_rs2[17]
  PIN o_ext_rs2[18]
    DIRECTION OUTPUT ;
    USE SIGNAL ;
    ANTENNADIFFAREA 0.702900 ;
    PORT
      LAYER met3 ;
        RECT 160.400 66.680 161.000 67.280 ;
    END
  END o_ext_rs2[18]
  PIN o_ext_rs2[19]
    DIRECTION OUTPUT ;
    USE SIGNAL ;
    ANTENNADIFFAREA 0.702900 ;
    PORT
      LAYER met3 ;
        RECT 160.400 61.240 161.000 61.840 ;
    END
  END o_ext_rs2[19]
  PIN o_ext_rs2[1]
    DIRECTION OUTPUT ;
    USE SIGNAL ;
    ANTENNADIFFAREA 0.702900 ;
    PORT
      LAYER met3 ;
        RECT 160.400 108.840 161.000 109.440 ;
    END
  END o_ext_rs2[1]
  PIN o_ext_rs2[20]
    DIRECTION OUTPUT ;
    USE SIGNAL ;
    ANTENNADIFFAREA 0.702900 ;
    PORT
      LAYER met3 ;
        RECT 160.400 36.760 161.000 37.360 ;
    END
  END o_ext_rs2[20]
  PIN o_ext_rs2[21]
    DIRECTION OUTPUT ;
    USE SIGNAL ;
    ANTENNADIFFAREA 0.702900 ;
    PORT
      LAYER met3 ;
        RECT 160.400 43.560 161.000 44.160 ;
    END
  END o_ext_rs2[21]
  PIN o_ext_rs2[22]
    DIRECTION OUTPUT ;
    USE SIGNAL ;
    ANTENNADIFFAREA 0.702900 ;
    PORT
      LAYER met3 ;
        RECT 160.400 50.360 161.000 50.960 ;
    END
  END o_ext_rs2[22]
  PIN o_ext_rs2[23]
    DIRECTION OUTPUT ;
    USE SIGNAL ;
    ANTENNADIFFAREA 0.702900 ;
    PORT
      LAYER met3 ;
        RECT 160.400 46.280 161.000 46.880 ;
    END
  END o_ext_rs2[23]
  PIN o_ext_rs2[24]
    DIRECTION OUTPUT ;
    USE SIGNAL ;
    ANTENNADIFFAREA 0.702900 ;
    PORT
      LAYER met3 ;
        RECT 160.400 84.360 161.000 84.960 ;
    END
  END o_ext_rs2[24]
  PIN o_ext_rs2[25]
    DIRECTION OUTPUT ;
    USE SIGNAL ;
    ANTENNADIFFAREA 0.702900 ;
    PORT
      LAYER met3 ;
        RECT 160.400 69.400 161.000 70.000 ;
    END
  END o_ext_rs2[25]
  PIN o_ext_rs2[26]
    DIRECTION OUTPUT ;
    USE SIGNAL ;
    ANTENNADIFFAREA 0.702900 ;
    PORT
      LAYER met2 ;
        RECT 120.610 0.000 120.890 0.280 ;
    END
  END o_ext_rs2[26]
  PIN o_ext_rs2[27]
    DIRECTION OUTPUT ;
    USE SIGNAL ;
    ANTENNADIFFAREA 0.702900 ;
    PORT
      LAYER met2 ;
        RECT 113.250 0.000 113.530 0.280 ;
    END
  END o_ext_rs2[27]
  PIN o_ext_rs2[28]
    DIRECTION OUTPUT ;
    USE SIGNAL ;
    ANTENNADIFFAREA 0.702900 ;
    PORT
      LAYER met2 ;
        RECT 100.370 0.000 100.650 0.280 ;
    END
  END o_ext_rs2[28]
  PIN o_ext_rs2[29]
    DIRECTION OUTPUT ;
    USE SIGNAL ;
    ANTENNADIFFAREA 0.702900 ;
    PORT
      LAYER met2 ;
        RECT 101.290 0.000 101.570 0.280 ;
    END
  END o_ext_rs2[29]
  PIN o_ext_rs2[2]
    DIRECTION OUTPUT ;
    USE SIGNAL ;
    ANTENNADIFFAREA 0.702900 ;
    PORT
      LAYER met3 ;
        RECT 160.400 127.880 161.000 128.480 ;
    END
  END o_ext_rs2[2]
  PIN o_ext_rs2[30]
    DIRECTION OUTPUT ;
    USE SIGNAL ;
    ANTENNADIFFAREA 0.702900 ;
    PORT
      LAYER met2 ;
        RECT 94.850 0.000 95.130 0.280 ;
    END
  END o_ext_rs2[30]
  PIN o_ext_rs2[31]
    DIRECTION OUTPUT ;
    USE SIGNAL ;
    ANTENNADIFFAREA 0.702900 ;
    PORT
      LAYER met2 ;
        RECT 91.170 0.000 91.450 0.280 ;
    END
  END o_ext_rs2[31]
  PIN o_ext_rs2[3]
    DIRECTION OUTPUT ;
    USE SIGNAL ;
    ANTENNADIFFAREA 0.702900 ;
    PORT
      LAYER met3 ;
        RECT 160.400 134.680 161.000 135.280 ;
    END
  END o_ext_rs2[3]
  PIN o_ext_rs2[4]
    DIRECTION OUTPUT ;
    USE SIGNAL ;
    ANTENNADIFFAREA 0.702900 ;
    PORT
      LAYER met3 ;
        RECT 160.400 125.160 161.000 125.760 ;
    END
  END o_ext_rs2[4]
  PIN o_ext_rs2[5]
    DIRECTION OUTPUT ;
    USE SIGNAL ;
    ANTENNADIFFAREA 0.702900 ;
    PORT
      LAYER met3 ;
        RECT 160.400 130.600 161.000 131.200 ;
    END
  END o_ext_rs2[5]
  PIN o_ext_rs2[6]
    DIRECTION OUTPUT ;
    USE SIGNAL ;
    ANTENNADIFFAREA 0.702900 ;
    PORT
      LAYER met3 ;
        RECT 160.400 133.320 161.000 133.920 ;
    END
  END o_ext_rs2[6]
  PIN o_ext_rs2[7]
    DIRECTION OUTPUT ;
    USE SIGNAL ;
    ANTENNADIFFAREA 0.702900 ;
    PORT
      LAYER met3 ;
        RECT 160.400 107.480 161.000 108.080 ;
    END
  END o_ext_rs2[7]
  PIN o_ext_rs2[8]
    DIRECTION OUTPUT ;
    USE SIGNAL ;
    ANTENNADIFFAREA 0.702900 ;
    PORT
      LAYER met3 ;
        RECT 160.400 96.600 161.000 97.200 ;
    END
  END o_ext_rs2[8]
  PIN o_ext_rs2[9]
    DIRECTION OUTPUT ;
    USE SIGNAL ;
    ANTENNADIFFAREA 0.702900 ;
    PORT
      LAYER met3 ;
        RECT 160.400 104.760 161.000 105.360 ;
    END
  END o_ext_rs2[9]
  PIN o_ibus_adr[0]
    DIRECTION OUTPUT ;
    USE SIGNAL ;
    ANTENNADIFFAREA 0.702900 ;
    PORT
      LAYER met2 ;
        RECT 98.530 225.480 98.810 225.760 ;
    END
  END o_ibus_adr[0]
  PIN o_ibus_adr[10]
    DIRECTION OUTPUT ;
    USE SIGNAL ;
    ANTENNADIFFAREA 0.702900 ;
    PORT
      LAYER met3 ;
        RECT 160.400 174.120 161.000 174.720 ;
    END
  END o_ibus_adr[10]
  PIN o_ibus_adr[11]
    DIRECTION OUTPUT ;
    USE SIGNAL ;
    ANTENNADIFFAREA 0.702900 ;
    PORT
      LAYER met2 ;
        RECT 134.410 225.480 134.690 225.760 ;
    END
  END o_ibus_adr[11]
  PIN o_ibus_adr[12]
    DIRECTION OUTPUT ;
    USE SIGNAL ;
    ANTENNADIFFAREA 0.702900 ;
    PORT
      LAYER met2 ;
        RECT 137.170 225.480 137.450 225.760 ;
    END
  END o_ibus_adr[12]
  PIN o_ibus_adr[13]
    DIRECTION OUTPUT ;
    USE SIGNAL ;
    ANTENNADIFFAREA 0.702900 ;
    PORT
      LAYER met2 ;
        RECT 141.770 225.480 142.050 225.760 ;
    END
  END o_ibus_adr[13]
  PIN o_ibus_adr[14]
    DIRECTION OUTPUT ;
    USE SIGNAL ;
    ANTENNADIFFAREA 0.702900 ;
    PORT
      LAYER met3 ;
        RECT 160.400 189.080 161.000 189.680 ;
    END
  END o_ibus_adr[14]
  PIN o_ibus_adr[15]
    DIRECTION OUTPUT ;
    USE SIGNAL ;
    ANTENNADIFFAREA 0.702900 ;
    PORT
      LAYER met3 ;
        RECT 160.400 186.360 161.000 186.960 ;
    END
  END o_ibus_adr[15]
  PIN o_ibus_adr[16]
    DIRECTION OUTPUT ;
    USE SIGNAL ;
    ANTENNADIFFAREA 0.702900 ;
    PORT
      LAYER met3 ;
        RECT 160.400 180.920 161.000 181.520 ;
    END
  END o_ibus_adr[16]
  PIN o_ibus_adr[17]
    DIRECTION OUTPUT ;
    USE SIGNAL ;
    ANTENNADIFFAREA 0.702900 ;
    PORT
      LAYER met3 ;
        RECT 160.400 175.480 161.000 176.080 ;
    END
  END o_ibus_adr[17]
  PIN o_ibus_adr[18]
    DIRECTION OUTPUT ;
    USE SIGNAL ;
    ANTENNADIFFAREA 0.702900 ;
    PORT
      LAYER met3 ;
        RECT 160.400 172.760 161.000 173.360 ;
    END
  END o_ibus_adr[18]
  PIN o_ibus_adr[19]
    DIRECTION OUTPUT ;
    USE SIGNAL ;
    ANTENNADIFFAREA 0.702900 ;
    PORT
      LAYER met3 ;
        RECT 160.400 164.600 161.000 165.200 ;
    END
  END o_ibus_adr[19]
  PIN o_ibus_adr[1]
    DIRECTION OUTPUT ;
    USE SIGNAL ;
    ANTENNADIFFAREA 0.702900 ;
    PORT
      LAYER met2 ;
        RECT 104.970 225.480 105.250 225.760 ;
    END
  END o_ibus_adr[1]
  PIN o_ibus_adr[20]
    DIRECTION OUTPUT ;
    USE SIGNAL ;
    ANTENNADIFFAREA 0.702900 ;
    PORT
      LAYER met3 ;
        RECT 160.400 159.160 161.000 159.760 ;
    END
  END o_ibus_adr[20]
  PIN o_ibus_adr[21]
    DIRECTION OUTPUT ;
    USE SIGNAL ;
    ANTENNADIFFAREA 0.702900 ;
    PORT
      LAYER met3 ;
        RECT 160.400 157.800 161.000 158.400 ;
    END
  END o_ibus_adr[21]
  PIN o_ibus_adr[22]
    DIRECTION OUTPUT ;
    USE SIGNAL ;
    ANTENNADIFFAREA 0.702900 ;
    PORT
      LAYER met3 ;
        RECT 160.400 156.440 161.000 157.040 ;
    END
  END o_ibus_adr[22]
  PIN o_ibus_adr[23]
    DIRECTION OUTPUT ;
    USE SIGNAL ;
    ANTENNADIFFAREA 0.702900 ;
    PORT
      LAYER met3 ;
        RECT 160.400 155.080 161.000 155.680 ;
    END
  END o_ibus_adr[23]
  PIN o_ibus_adr[24]
    DIRECTION OUTPUT ;
    USE SIGNAL ;
    ANTENNADIFFAREA 0.702900 ;
    PORT
      LAYER met3 ;
        RECT 160.400 148.280 161.000 148.880 ;
    END
  END o_ibus_adr[24]
  PIN o_ibus_adr[25]
    DIRECTION OUTPUT ;
    USE SIGNAL ;
    ANTENNADIFFAREA 0.702900 ;
    PORT
      LAYER met3 ;
        RECT 160.400 145.560 161.000 146.160 ;
    END
  END o_ibus_adr[25]
  PIN o_ibus_adr[26]
    DIRECTION OUTPUT ;
    USE SIGNAL ;
    ANTENNADIFFAREA 0.702900 ;
    PORT
      LAYER met3 ;
        RECT 160.400 149.640 161.000 150.240 ;
    END
  END o_ibus_adr[26]
  PIN o_ibus_adr[27]
    DIRECTION OUTPUT ;
    USE SIGNAL ;
    ANTENNADIFFAREA 0.702900 ;
    PORT
      LAYER met3 ;
        RECT 160.400 152.360 161.000 152.960 ;
    END
  END o_ibus_adr[27]
  PIN o_ibus_adr[28]
    DIRECTION OUTPUT ;
    USE SIGNAL ;
    ANTENNADIFFAREA 0.702900 ;
    PORT
      LAYER met3 ;
        RECT 160.400 151.000 161.000 151.600 ;
    END
  END o_ibus_adr[28]
  PIN o_ibus_adr[29]
    DIRECTION OUTPUT ;
    USE SIGNAL ;
    ANTENNADIFFAREA 0.702900 ;
    PORT
      LAYER met3 ;
        RECT 160.400 153.720 161.000 154.320 ;
    END
  END o_ibus_adr[29]
  PIN o_ibus_adr[2]
    DIRECTION OUTPUT ;
    USE SIGNAL ;
    ANTENNADIFFAREA 0.702900 ;
    PORT
      LAYER met2 ;
        RECT 108.650 225.480 108.930 225.760 ;
    END
  END o_ibus_adr[2]
  PIN o_ibus_adr[30]
    DIRECTION OUTPUT ;
    USE SIGNAL ;
    ANTENNADIFFAREA 0.702900 ;
    PORT
      LAYER met3 ;
        RECT 160.400 146.920 161.000 147.520 ;
    END
  END o_ibus_adr[30]
  PIN o_ibus_adr[31]
    DIRECTION OUTPUT ;
    USE SIGNAL ;
    ANTENNADIFFAREA 0.702900 ;
    PORT
      LAYER met3 ;
        RECT 160.400 144.200 161.000 144.800 ;
    END
  END o_ibus_adr[31]
  PIN o_ibus_adr[3]
    DIRECTION OUTPUT ;
    USE SIGNAL ;
    ANTENNADIFFAREA 0.702900 ;
    PORT
      LAYER met2 ;
        RECT 114.170 225.480 114.450 225.760 ;
    END
  END o_ibus_adr[3]
  PIN o_ibus_adr[4]
    DIRECTION OUTPUT ;
    USE SIGNAL ;
    ANTENNADIFFAREA 0.702900 ;
    PORT
      LAYER met2 ;
        RECT 117.850 225.480 118.130 225.760 ;
    END
  END o_ibus_adr[4]
  PIN o_ibus_adr[5]
    DIRECTION OUTPUT ;
    USE SIGNAL ;
    ANTENNADIFFAREA 0.702900 ;
    PORT
      LAYER met2 ;
        RECT 119.690 225.480 119.970 225.760 ;
    END
  END o_ibus_adr[5]
  PIN o_ibus_adr[6]
    DIRECTION OUTPUT ;
    USE SIGNAL ;
    ANTENNADIFFAREA 0.702900 ;
    PORT
      LAYER met2 ;
        RECT 122.450 225.480 122.730 225.760 ;
    END
  END o_ibus_adr[6]
  PIN o_ibus_adr[7]
    DIRECTION OUTPUT ;
    USE SIGNAL ;
    ANTENNADIFFAREA 0.702900 ;
    PORT
      LAYER met2 ;
        RECT 124.290 225.480 124.570 225.760 ;
    END
  END o_ibus_adr[7]
  PIN o_ibus_adr[8]
    DIRECTION OUTPUT ;
    USE SIGNAL ;
    ANTENNADIFFAREA 0.702900 ;
    PORT
      LAYER met3 ;
        RECT 160.400 170.040 161.000 170.640 ;
    END
  END o_ibus_adr[8]
  PIN o_ibus_adr[9]
    DIRECTION OUTPUT ;
    USE SIGNAL ;
    ANTENNADIFFAREA 0.702900 ;
    PORT
      LAYER met3 ;
        RECT 160.400 171.400 161.000 172.000 ;
    END
  END o_ibus_adr[9]
  PIN o_ibus_cyc
    DIRECTION OUTPUT ;
    USE SIGNAL ;
    ANTENNADIFFAREA 0.702900 ;
    PORT
      LAYER met2 ;
        RECT 91.170 225.480 91.450 225.760 ;
    END
  END o_ibus_cyc
  PIN o_mdu_valid
    DIRECTION OUTPUT ;
    USE SIGNAL ;
    PORT
      LAYER met3 ;
        RECT 0.000 55.800 0.600 56.400 ;
    END
  END o_mdu_valid
  PIN o_rf_rreq
    DIRECTION OUTPUT ;
    USE SIGNAL ;
    ANTENNADIFFAREA 0.702900 ;
    PORT
      LAYER met2 ;
        RECT 74.610 225.480 74.890 225.760 ;
    END
  END o_rf_rreq
  PIN o_rf_wreq
    DIRECTION OUTPUT ;
    USE SIGNAL ;
    ANTENNADIFFAREA 0.702900 ;
    PORT
      LAYER met3 ;
        RECT 160.400 112.920 161.000 113.520 ;
    END
  END o_rf_wreq
  PIN o_rreg0[0]
    DIRECTION OUTPUT ;
    USE SIGNAL ;
    ANTENNADIFFAREA 0.702900 ;
    PORT
      LAYER met3 ;
        RECT 0.000 76.200 0.600 76.800 ;
    END
  END o_rreg0[0]
  PIN o_rreg0[1]
    DIRECTION OUTPUT ;
    USE SIGNAL ;
    ANTENNADIFFAREA 0.702900 ;
    PORT
      LAYER met3 ;
        RECT 0.000 73.480 0.600 74.080 ;
    END
  END o_rreg0[1]
  PIN o_rreg0[2]
    DIRECTION OUTPUT ;
    USE SIGNAL ;
    ANTENNADIFFAREA 0.702900 ;
    PORT
      LAYER met3 ;
        RECT 0.000 80.280 0.600 80.880 ;
    END
  END o_rreg0[2]
  PIN o_rreg0[3]
    DIRECTION OUTPUT ;
    USE SIGNAL ;
    ANTENNADIFFAREA 0.702900 ;
    PORT
      LAYER met3 ;
        RECT 0.000 93.880 0.600 94.480 ;
    END
  END o_rreg0[3]
  PIN o_rreg0[4]
    DIRECTION OUTPUT ;
    USE SIGNAL ;
    ANTENNADIFFAREA 0.702900 ;
    PORT
      LAYER met3 ;
        RECT 0.000 103.400 0.600 104.000 ;
    END
  END o_rreg0[4]
  PIN o_rreg0[5]
    DIRECTION OUTPUT ;
    USE SIGNAL ;
    PORT
      LAYER met2 ;
        RECT 145.450 0.000 145.730 0.280 ;
    END
  END o_rreg0[5]
  PIN o_rreg1[0]
    DIRECTION OUTPUT ;
    USE SIGNAL ;
    ANTENNADIFFAREA 0.702900 ;
    PORT
      LAYER met2 ;
        RECT 48.850 225.480 49.130 225.760 ;
    END
  END o_rreg1[0]
  PIN o_rreg1[1]
    DIRECTION OUTPUT ;
    USE SIGNAL ;
    ANTENNADIFFAREA 0.702900 ;
    PORT
      LAYER met2 ;
        RECT 45.170 225.480 45.450 225.760 ;
    END
  END o_rreg1[1]
  PIN o_rreg1[2]
    DIRECTION OUTPUT ;
    USE SIGNAL ;
    ANTENNADIFFAREA 0.702900 ;
    PORT
      LAYER met2 ;
        RECT 47.010 225.480 47.290 225.760 ;
    END
  END o_rreg1[2]
  PIN o_rreg1[3]
    DIRECTION OUTPUT ;
    USE SIGNAL ;
    ANTENNADIFFAREA 0.702900 ;
    PORT
      LAYER met2 ;
        RECT 43.330 225.480 43.610 225.760 ;
    END
  END o_rreg1[3]
  PIN o_rreg1[4]
    DIRECTION OUTPUT ;
    USE SIGNAL ;
    ANTENNADIFFAREA 0.702900 ;
    PORT
      LAYER met2 ;
        RECT 39.650 225.480 39.930 225.760 ;
    END
  END o_rreg1[4]
  PIN o_rreg1[5]
    DIRECTION OUTPUT ;
    USE SIGNAL ;
    ANTENNADIFFAREA 0.702900 ;
    PORT
      LAYER met2 ;
        RECT 44.250 225.480 44.530 225.760 ;
    END
  END o_rreg1[5]
  PIN o_wdata0
    DIRECTION OUTPUT ;
    USE SIGNAL ;
    ANTENNADIFFAREA 0.702900 ;
    PORT
      LAYER met3 ;
        RECT 0.000 121.080 0.600 121.680 ;
    END
  END o_wdata0
  PIN o_wdata1
    DIRECTION OUTPUT ;
    USE SIGNAL ;
    ANTENNADIFFAREA 0.702900 ;
    PORT
      LAYER met2 ;
        RECT 66.330 225.480 66.610 225.760 ;
    END
  END o_wdata1
  PIN o_wen0
    DIRECTION OUTPUT ;
    USE SIGNAL ;
    ANTENNADIFFAREA 0.702900 ;
    PORT
      LAYER met3 ;
        RECT 0.000 153.720 0.600 154.320 ;
    END
  END o_wen0
  PIN o_wen1
    DIRECTION OUTPUT ;
    USE SIGNAL ;
    ANTENNADIFFAREA 0.702900 ;
    PORT
      LAYER met2 ;
        RECT 49.770 225.480 50.050 225.760 ;
    END
  END o_wen1
  PIN o_wreg0[0]
    DIRECTION OUTPUT ;
    USE SIGNAL ;
    ANTENNADIFFAREA 0.702900 ;
    PORT
      LAYER met3 ;
        RECT 0.000 136.040 0.600 136.640 ;
    END
  END o_wreg0[0]
  PIN o_wreg0[1]
    DIRECTION OUTPUT ;
    USE SIGNAL ;
    ANTENNADIFFAREA 0.702900 ;
    PORT
      LAYER met3 ;
        RECT 0.000 149.640 0.600 150.240 ;
    END
  END o_wreg0[1]
  PIN o_wreg0[2]
    DIRECTION OUTPUT ;
    USE SIGNAL ;
    ANTENNADIFFAREA 0.702900 ;
    PORT
      LAYER met3 ;
        RECT 0.000 148.280 0.600 148.880 ;
    END
  END o_wreg0[2]
  PIN o_wreg0[3]
    DIRECTION OUTPUT ;
    USE SIGNAL ;
    ANTENNADIFFAREA 0.702900 ;
    PORT
      LAYER met3 ;
        RECT 0.000 152.360 0.600 152.960 ;
    END
  END o_wreg0[3]
  PIN o_wreg0[4]
    DIRECTION OUTPUT ;
    USE SIGNAL ;
    ANTENNADIFFAREA 0.702900 ;
    PORT
      LAYER met3 ;
        RECT 0.000 155.080 0.600 155.680 ;
    END
  END o_wreg0[4]
  PIN o_wreg0[5]
    DIRECTION OUTPUT ;
    USE SIGNAL ;
    ANTENNADIFFAREA 0.702900 ;
    PORT
      LAYER met2 ;
        RECT 46.090 225.480 46.370 225.760 ;
    END
  END o_wreg0[5]
  PIN o_wreg1[0]
    DIRECTION OUTPUT ;
    USE SIGNAL ;
    ANTENNADIFFAREA 0.702900 ;
    PORT
      LAYER met2 ;
        RECT 51.610 225.480 51.890 225.760 ;
    END
  END o_wreg1[0]
  PIN o_wreg1[1]
    DIRECTION OUTPUT ;
    USE SIGNAL ;
    ANTENNADIFFAREA 0.702900 ;
    PORT
      LAYER met2 ;
        RECT 41.490 225.480 41.770 225.760 ;
    END
  END o_wreg1[1]
  PIN o_wreg1[2]
    DIRECTION OUTPUT ;
    USE SIGNAL ;
    PORT
      LAYER met3 ;
        RECT 0.000 65.320 0.600 65.920 ;
    END
  END o_wreg1[2]
  PIN o_wreg1[3]
    DIRECTION OUTPUT ;
    USE SIGNAL ;
    PORT
      LAYER met2 ;
        RECT 12.050 0.000 12.330 0.280 ;
    END
  END o_wreg1[3]
  PIN o_wreg1[4]
    DIRECTION OUTPUT ;
    USE SIGNAL ;
    PORT
      LAYER met3 ;
        RECT 0.000 66.680 0.600 67.280 ;
    END
  END o_wreg1[4]
  PIN o_wreg1[5]
    DIRECTION OUTPUT ;
    USE SIGNAL ;
    PORT
      LAYER met2 ;
        RECT 148.210 225.480 148.490 225.760 ;
    END
  END o_wreg1[5]
  OBS
      LAYER nwell ;
        RECT 5.330 10.795 155.670 215.070 ;
      LAYER li1 ;
        RECT 5.520 10.795 155.480 214.965 ;
      LAYER met1 ;
        RECT 0.530 0.040 160.010 215.120 ;
      LAYER met2 ;
        RECT 0.550 225.200 12.690 225.690 ;
        RECT 13.530 225.200 29.250 225.690 ;
        RECT 30.090 225.200 35.690 225.690 ;
        RECT 36.530 225.200 39.370 225.690 ;
        RECT 40.210 225.200 41.210 225.690 ;
        RECT 42.050 225.200 43.050 225.690 ;
        RECT 43.890 225.200 43.970 225.690 ;
        RECT 44.810 225.200 44.890 225.690 ;
        RECT 45.730 225.200 45.810 225.690 ;
        RECT 46.650 225.200 46.730 225.690 ;
        RECT 47.570 225.200 47.650 225.690 ;
        RECT 48.490 225.200 48.570 225.690 ;
        RECT 49.410 225.200 49.490 225.690 ;
        RECT 50.330 225.200 50.410 225.690 ;
        RECT 51.250 225.200 51.330 225.690 ;
        RECT 52.170 225.200 53.170 225.690 ;
        RECT 54.010 225.200 56.850 225.690 ;
        RECT 57.690 225.200 66.050 225.690 ;
        RECT 66.890 225.200 69.730 225.690 ;
        RECT 70.570 225.200 70.650 225.690 ;
        RECT 71.490 225.200 74.330 225.690 ;
        RECT 75.170 225.200 78.930 225.690 ;
        RECT 79.770 225.200 90.890 225.690 ;
        RECT 91.730 225.200 98.250 225.690 ;
        RECT 99.090 225.200 104.690 225.690 ;
        RECT 105.530 225.200 105.610 225.690 ;
        RECT 106.450 225.200 108.370 225.690 ;
        RECT 109.210 225.200 113.890 225.690 ;
        RECT 114.730 225.200 117.570 225.690 ;
        RECT 118.410 225.200 119.410 225.690 ;
        RECT 120.250 225.200 122.170 225.690 ;
        RECT 123.010 225.200 124.010 225.690 ;
        RECT 124.850 225.200 134.130 225.690 ;
        RECT 134.970 225.200 136.890 225.690 ;
        RECT 137.730 225.200 141.490 225.690 ;
        RECT 142.330 225.200 147.930 225.690 ;
        RECT 148.770 225.200 159.990 225.690 ;
        RECT 0.550 0.560 159.990 225.200 ;
        RECT 0.550 0.010 1.650 0.560 ;
        RECT 2.490 0.010 2.570 0.560 ;
        RECT 3.410 0.010 3.490 0.560 ;
        RECT 4.330 0.010 4.410 0.560 ;
        RECT 5.250 0.010 5.330 0.560 ;
        RECT 6.170 0.010 6.250 0.560 ;
        RECT 7.090 0.010 7.170 0.560 ;
        RECT 8.010 0.010 8.090 0.560 ;
        RECT 8.930 0.010 9.010 0.560 ;
        RECT 9.850 0.010 9.930 0.560 ;
        RECT 10.770 0.010 10.850 0.560 ;
        RECT 11.690 0.010 11.770 0.560 ;
        RECT 12.610 0.010 12.690 0.560 ;
        RECT 13.530 0.010 13.610 0.560 ;
        RECT 14.450 0.010 14.530 0.560 ;
        RECT 15.370 0.010 15.450 0.560 ;
        RECT 16.290 0.010 16.370 0.560 ;
        RECT 17.210 0.010 17.290 0.560 ;
        RECT 18.130 0.010 18.210 0.560 ;
        RECT 19.050 0.010 19.130 0.560 ;
        RECT 19.970 0.010 20.050 0.560 ;
        RECT 20.890 0.010 20.970 0.560 ;
        RECT 21.810 0.010 21.890 0.560 ;
        RECT 22.730 0.010 22.810 0.560 ;
        RECT 23.650 0.010 23.730 0.560 ;
        RECT 24.570 0.010 24.650 0.560 ;
        RECT 25.490 0.010 25.570 0.560 ;
        RECT 26.410 0.010 26.490 0.560 ;
        RECT 27.330 0.010 27.410 0.560 ;
        RECT 28.250 0.010 28.330 0.560 ;
        RECT 29.170 0.010 29.250 0.560 ;
        RECT 30.090 0.010 30.170 0.560 ;
        RECT 31.010 0.010 31.090 0.560 ;
        RECT 31.930 0.010 32.010 0.560 ;
        RECT 32.850 0.010 32.930 0.560 ;
        RECT 33.770 0.010 33.850 0.560 ;
        RECT 34.690 0.010 34.770 0.560 ;
        RECT 35.610 0.010 35.690 0.560 ;
        RECT 36.530 0.010 36.610 0.560 ;
        RECT 37.450 0.010 37.530 0.560 ;
        RECT 38.370 0.010 38.450 0.560 ;
        RECT 39.290 0.010 39.370 0.560 ;
        RECT 40.210 0.010 40.290 0.560 ;
        RECT 41.130 0.010 41.210 0.560 ;
        RECT 42.050 0.010 42.130 0.560 ;
        RECT 42.970 0.010 43.050 0.560 ;
        RECT 43.890 0.010 43.970 0.560 ;
        RECT 44.810 0.010 44.890 0.560 ;
        RECT 45.730 0.010 45.810 0.560 ;
        RECT 46.650 0.010 46.730 0.560 ;
        RECT 47.570 0.010 47.650 0.560 ;
        RECT 48.490 0.010 48.570 0.560 ;
        RECT 49.410 0.010 49.490 0.560 ;
        RECT 50.330 0.010 50.410 0.560 ;
        RECT 51.250 0.010 51.330 0.560 ;
        RECT 52.170 0.010 52.250 0.560 ;
        RECT 53.090 0.010 53.170 0.560 ;
        RECT 54.010 0.010 54.090 0.560 ;
        RECT 54.930 0.010 55.010 0.560 ;
        RECT 55.850 0.010 55.930 0.560 ;
        RECT 56.770 0.010 56.850 0.560 ;
        RECT 57.690 0.010 57.770 0.560 ;
        RECT 58.610 0.010 58.690 0.560 ;
        RECT 59.530 0.010 59.610 0.560 ;
        RECT 60.450 0.010 60.530 0.560 ;
        RECT 61.370 0.010 61.450 0.560 ;
        RECT 62.290 0.010 62.370 0.560 ;
        RECT 63.210 0.010 63.290 0.560 ;
        RECT 64.130 0.010 64.210 0.560 ;
        RECT 65.050 0.010 65.130 0.560 ;
        RECT 65.970 0.010 66.050 0.560 ;
        RECT 66.890 0.010 66.970 0.560 ;
        RECT 67.810 0.010 67.890 0.560 ;
        RECT 68.730 0.010 68.810 0.560 ;
        RECT 69.650 0.010 69.730 0.560 ;
        RECT 70.570 0.010 70.650 0.560 ;
        RECT 71.490 0.010 71.570 0.560 ;
        RECT 72.410 0.010 72.490 0.560 ;
        RECT 73.330 0.010 73.410 0.560 ;
        RECT 74.250 0.010 74.330 0.560 ;
        RECT 75.170 0.010 75.250 0.560 ;
        RECT 76.090 0.010 76.170 0.560 ;
        RECT 77.010 0.010 77.090 0.560 ;
        RECT 77.930 0.010 78.010 0.560 ;
        RECT 78.850 0.010 78.930 0.560 ;
        RECT 79.770 0.010 79.850 0.560 ;
        RECT 80.690 0.010 80.770 0.560 ;
        RECT 81.610 0.010 81.690 0.560 ;
        RECT 82.530 0.010 82.610 0.560 ;
        RECT 83.450 0.010 83.530 0.560 ;
        RECT 84.370 0.010 87.210 0.560 ;
        RECT 88.050 0.010 89.050 0.560 ;
        RECT 89.890 0.010 89.970 0.560 ;
        RECT 90.810 0.010 90.890 0.560 ;
        RECT 91.730 0.010 91.810 0.560 ;
        RECT 92.650 0.010 92.730 0.560 ;
        RECT 93.570 0.010 93.650 0.560 ;
        RECT 94.490 0.010 94.570 0.560 ;
        RECT 95.410 0.010 95.490 0.560 ;
        RECT 96.330 0.010 96.410 0.560 ;
        RECT 97.250 0.010 97.330 0.560 ;
        RECT 98.170 0.010 98.250 0.560 ;
        RECT 99.090 0.010 100.090 0.560 ;
        RECT 100.930 0.010 101.010 0.560 ;
        RECT 101.850 0.010 107.450 0.560 ;
        RECT 108.290 0.010 110.210 0.560 ;
        RECT 111.050 0.010 111.130 0.560 ;
        RECT 111.970 0.010 112.050 0.560 ;
        RECT 112.890 0.010 112.970 0.560 ;
        RECT 113.810 0.010 113.890 0.560 ;
        RECT 114.730 0.010 114.810 0.560 ;
        RECT 115.650 0.010 120.330 0.560 ;
        RECT 121.170 0.010 145.170 0.560 ;
        RECT 146.010 0.010 146.090 0.560 ;
        RECT 146.930 0.010 159.990 0.560 ;
      LAYER met3 ;
        RECT 0.600 205.040 160.400 215.045 ;
        RECT 1.000 202.280 160.400 205.040 ;
        RECT 0.600 190.080 160.400 202.280 ;
        RECT 0.600 188.680 160.000 190.080 ;
        RECT 0.600 187.360 160.400 188.680 ;
        RECT 0.600 185.960 160.000 187.360 ;
        RECT 0.600 181.920 160.400 185.960 ;
        RECT 0.600 180.520 160.000 181.920 ;
        RECT 0.600 179.200 160.400 180.520 ;
        RECT 1.000 176.480 160.400 179.200 ;
        RECT 1.000 175.080 160.000 176.480 ;
        RECT 0.600 169.640 160.000 175.080 ;
        RECT 0.600 165.600 160.400 169.640 ;
        RECT 0.600 164.200 160.000 165.600 ;
        RECT 0.600 160.160 160.400 164.200 ;
        RECT 0.600 158.800 160.000 160.160 ;
        RECT 1.000 145.160 160.000 158.800 ;
        RECT 0.600 141.120 160.000 145.160 ;
        RECT 1.000 139.720 160.000 141.120 ;
        RECT 0.600 137.040 160.000 139.720 ;
        RECT 1.000 135.640 160.000 137.040 ;
        RECT 0.600 132.960 160.000 135.640 ;
        RECT 1.000 131.560 160.000 132.960 ;
        RECT 0.600 130.240 160.000 131.560 ;
        RECT 1.000 127.480 160.000 130.240 ;
        RECT 0.600 124.800 160.000 127.480 ;
        RECT 1.000 123.400 160.000 124.800 ;
        RECT 0.600 122.080 160.000 123.400 ;
        RECT 1.000 120.680 160.000 122.080 ;
        RECT 0.600 118.000 160.000 120.680 ;
        RECT 1.000 115.240 160.000 118.000 ;
        RECT 0.600 113.920 160.000 115.240 ;
        RECT 1.000 112.520 160.000 113.920 ;
        RECT 0.600 104.400 160.000 112.520 ;
        RECT 1.000 103.000 160.000 104.400 ;
        RECT 0.600 101.680 160.000 103.000 ;
        RECT 1.000 98.920 160.000 101.680 ;
        RECT 0.600 96.240 160.000 98.920 ;
        RECT 1.000 93.480 160.000 96.240 ;
        RECT 0.600 89.440 160.000 93.480 ;
        RECT 1.000 88.040 160.000 89.440 ;
        RECT 0.600 82.640 160.000 88.040 ;
        RECT 1.000 64.920 160.000 82.640 ;
        RECT 0.600 56.800 160.000 64.920 ;
        RECT 1.000 48.600 160.000 56.800 ;
        RECT 0.600 47.280 160.000 48.600 ;
        RECT 1.000 45.880 160.000 47.280 ;
        RECT 0.600 29.560 160.000 45.880 ;
        RECT 0.600 4.935 160.400 29.560 ;
      LAYER met4 ;
        RECT 18.695 10.240 20.640 209.945 ;
        RECT 23.040 10.240 23.940 209.945 ;
        RECT 26.340 10.240 151.505 209.945 ;
        RECT 18.695 4.935 151.505 10.240 ;
  END
END tt_um_serv_top
END LIBRARY

